# Generated by FakeRAM 2.0
VERSION 5.7 ;
BUSBITCHARS "[]" ;
PROPERTYDEFINITIONS
  MACRO width INTEGER ;
  MACRO depth INTEGER ;
  MACRO banks INTEGER ;
END PROPERTYDEFINITIONS
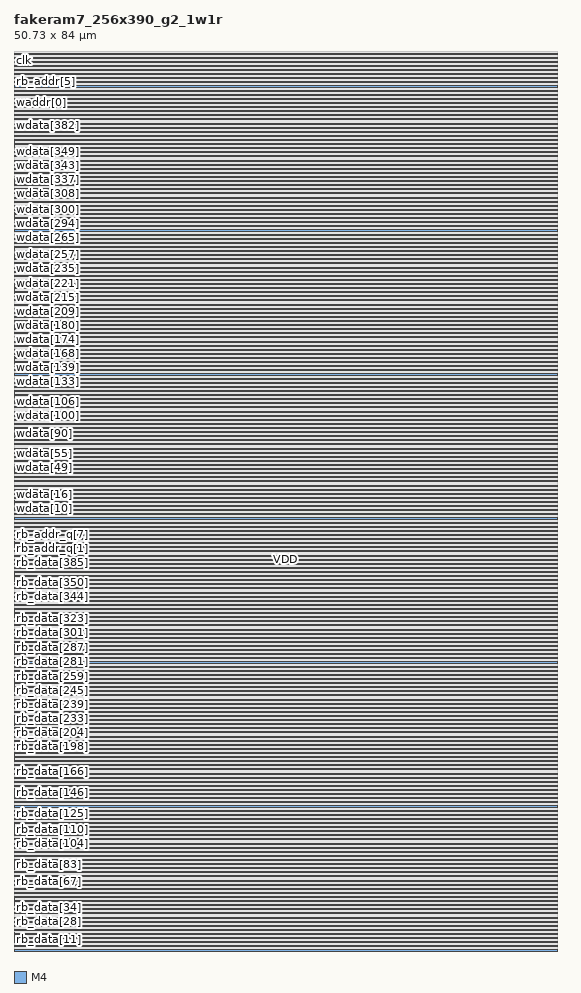
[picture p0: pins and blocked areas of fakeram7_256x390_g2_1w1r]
MACRO fakeram7_256x390_g2_1w1r
  PROPERTY width 390 ;
  PROPERTY depth 256 ;
  PROPERTY banks 1 ;
  FOREIGN fakeram7_256x390_g2_1w1r 0 0 ;
  SYMMETRY X Y R90 ;
  SIZE 50.7300 BY 84.0000 ;
  CLASS BLOCK ;
  PIN wdata[0]
    DIRECTION INPUT ;
    USE SIGNAL ;
    PORT
      LAYER M4 ;
      RECT 0.00000 40.36800 0.02400 40.39200 ;
    END
  END wdata[0]
  PIN wdata[1]
    DIRECTION INPUT ;
    USE SIGNAL ;
    PORT
      LAYER M4 ;
      RECT 0.00000 40.46400 0.02400 40.48800 ;
    END
  END wdata[1]
  PIN wdata[2]
    DIRECTION INPUT ;
    USE SIGNAL ;
    PORT
      LAYER M4 ;
      RECT 0.00000 40.56000 0.02400 40.58400 ;
    END
  END wdata[2]
  PIN wdata[3]
    DIRECTION INPUT ;
    USE SIGNAL ;
    PORT
      LAYER M4 ;
      RECT 0.00000 40.65600 0.02400 40.68000 ;
    END
  END wdata[3]
  PIN wdata[4]
    DIRECTION INPUT ;
    USE SIGNAL ;
    PORT
      LAYER M4 ;
      RECT 0.00000 40.75200 0.02400 40.77600 ;
    END
  END wdata[4]
  PIN wdata[5]
    DIRECTION INPUT ;
    USE SIGNAL ;
    PORT
      LAYER M4 ;
      RECT 0.00000 40.84800 0.02400 40.87200 ;
    END
  END wdata[5]
  PIN wdata[6]
    DIRECTION INPUT ;
    USE SIGNAL ;
    PORT
      LAYER M4 ;
      RECT 0.00000 40.94400 0.02400 40.96800 ;
    END
  END wdata[6]
  PIN wdata[7]
    DIRECTION INPUT ;
    USE SIGNAL ;
    PORT
      LAYER M4 ;
      RECT 0.00000 41.04000 0.02400 41.06400 ;
    END
  END wdata[7]
  PIN wdata[8]
    DIRECTION INPUT ;
    USE SIGNAL ;
    PORT
      LAYER M4 ;
      RECT 0.00000 41.13600 0.02400 41.16000 ;
    END
  END wdata[8]
  PIN wdata[9]
    DIRECTION INPUT ;
    USE SIGNAL ;
    PORT
      LAYER M4 ;
      RECT 0.00000 41.23200 0.02400 41.25600 ;
    END
  END wdata[9]
  PIN wdata[10]
    DIRECTION INPUT ;
    USE SIGNAL ;
    PORT
      LAYER M4 ;
      RECT 0.00000 41.32800 0.02400 41.35200 ;
    END
  END wdata[10]
  PIN wdata[11]
    DIRECTION INPUT ;
    USE SIGNAL ;
    PORT
      LAYER M4 ;
      RECT 0.00000 41.42400 0.02400 41.44800 ;
    END
  END wdata[11]
  PIN wdata[12]
    DIRECTION INPUT ;
    USE SIGNAL ;
    PORT
      LAYER M4 ;
      RECT 0.00000 41.52000 0.02400 41.54400 ;
    END
  END wdata[12]
  PIN wdata[13]
    DIRECTION INPUT ;
    USE SIGNAL ;
    PORT
      LAYER M4 ;
      RECT 0.00000 41.61600 0.02400 41.64000 ;
    END
  END wdata[13]
  PIN wdata[14]
    DIRECTION INPUT ;
    USE SIGNAL ;
    PORT
      LAYER M4 ;
      RECT 0.00000 41.71200 0.02400 41.73600 ;
    END
  END wdata[14]
  PIN wdata[15]
    DIRECTION INPUT ;
    USE SIGNAL ;
    PORT
      LAYER M4 ;
      RECT 0.00000 41.80800 0.02400 41.83200 ;
    END
  END wdata[15]
  PIN wdata[16]
    DIRECTION INPUT ;
    USE SIGNAL ;
    PORT
      LAYER M4 ;
      RECT 0.00000 41.90400 0.02400 41.92800 ;
    END
  END wdata[16]
  PIN wdata[17]
    DIRECTION INPUT ;
    USE SIGNAL ;
    PORT
      LAYER M4 ;
      RECT 0.00000 42.00000 0.02400 42.02400 ;
    END
  END wdata[17]
  PIN wdata[18]
    DIRECTION INPUT ;
    USE SIGNAL ;
    PORT
      LAYER M4 ;
      RECT 0.00000 42.09600 0.02400 42.12000 ;
    END
  END wdata[18]
  PIN wdata[19]
    DIRECTION INPUT ;
    USE SIGNAL ;
    PORT
      LAYER M4 ;
      RECT 0.00000 42.19200 0.02400 42.21600 ;
    END
  END wdata[19]
  PIN wdata[20]
    DIRECTION INPUT ;
    USE SIGNAL ;
    PORT
      LAYER M4 ;
      RECT 0.00000 42.28800 0.02400 42.31200 ;
    END
  END wdata[20]
  PIN wdata[21]
    DIRECTION INPUT ;
    USE SIGNAL ;
    PORT
      LAYER M4 ;
      RECT 0.00000 42.38400 0.02400 42.40800 ;
    END
  END wdata[21]
  PIN wdata[22]
    DIRECTION INPUT ;
    USE SIGNAL ;
    PORT
      LAYER M4 ;
      RECT 0.00000 42.48000 0.02400 42.50400 ;
    END
  END wdata[22]
  PIN wdata[23]
    DIRECTION INPUT ;
    USE SIGNAL ;
    PORT
      LAYER M4 ;
      RECT 0.00000 42.57600 0.02400 42.60000 ;
    END
  END wdata[23]
  PIN wdata[24]
    DIRECTION INPUT ;
    USE SIGNAL ;
    PORT
      LAYER M4 ;
      RECT 0.00000 42.67200 0.02400 42.69600 ;
    END
  END wdata[24]
  PIN wdata[25]
    DIRECTION INPUT ;
    USE SIGNAL ;
    PORT
      LAYER M4 ;
      RECT 0.00000 42.76800 0.02400 42.79200 ;
    END
  END wdata[25]
  PIN wdata[26]
    DIRECTION INPUT ;
    USE SIGNAL ;
    PORT
      LAYER M4 ;
      RECT 0.00000 42.86400 0.02400 42.88800 ;
    END
  END wdata[26]
  PIN wdata[27]
    DIRECTION INPUT ;
    USE SIGNAL ;
    PORT
      LAYER M4 ;
      RECT 0.00000 42.96000 0.02400 42.98400 ;
    END
  END wdata[27]
  PIN wdata[28]
    DIRECTION INPUT ;
    USE SIGNAL ;
    PORT
      LAYER M4 ;
      RECT 0.00000 43.05600 0.02400 43.08000 ;
    END
  END wdata[28]
  PIN wdata[29]
    DIRECTION INPUT ;
    USE SIGNAL ;
    PORT
      LAYER M4 ;
      RECT 0.00000 43.15200 0.02400 43.17600 ;
    END
  END wdata[29]
  PIN wdata[30]
    DIRECTION INPUT ;
    USE SIGNAL ;
    PORT
      LAYER M4 ;
      RECT 0.00000 43.24800 0.02400 43.27200 ;
    END
  END wdata[30]
  PIN wdata[31]
    DIRECTION INPUT ;
    USE SIGNAL ;
    PORT
      LAYER M4 ;
      RECT 0.00000 43.34400 0.02400 43.36800 ;
    END
  END wdata[31]
  PIN wdata[32]
    DIRECTION INPUT ;
    USE SIGNAL ;
    PORT
      LAYER M4 ;
      RECT 0.00000 43.44000 0.02400 43.46400 ;
    END
  END wdata[32]
  PIN wdata[33]
    DIRECTION INPUT ;
    USE SIGNAL ;
    PORT
      LAYER M4 ;
      RECT 0.00000 43.53600 0.02400 43.56000 ;
    END
  END wdata[33]
  PIN wdata[34]
    DIRECTION INPUT ;
    USE SIGNAL ;
    PORT
      LAYER M4 ;
      RECT 0.00000 43.63200 0.02400 43.65600 ;
    END
  END wdata[34]
  PIN wdata[35]
    DIRECTION INPUT ;
    USE SIGNAL ;
    PORT
      LAYER M4 ;
      RECT 0.00000 43.72800 0.02400 43.75200 ;
    END
  END wdata[35]
  PIN wdata[36]
    DIRECTION INPUT ;
    USE SIGNAL ;
    PORT
      LAYER M4 ;
      RECT 0.00000 43.82400 0.02400 43.84800 ;
    END
  END wdata[36]
  PIN wdata[37]
    DIRECTION INPUT ;
    USE SIGNAL ;
    PORT
      LAYER M4 ;
      RECT 0.00000 43.92000 0.02400 43.94400 ;
    END
  END wdata[37]
  PIN wdata[38]
    DIRECTION INPUT ;
    USE SIGNAL ;
    PORT
      LAYER M4 ;
      RECT 0.00000 44.01600 0.02400 44.04000 ;
    END
  END wdata[38]
  PIN wdata[39]
    DIRECTION INPUT ;
    USE SIGNAL ;
    PORT
      LAYER M4 ;
      RECT 0.00000 44.11200 0.02400 44.13600 ;
    END
  END wdata[39]
  PIN wdata[40]
    DIRECTION INPUT ;
    USE SIGNAL ;
    PORT
      LAYER M4 ;
      RECT 0.00000 44.20800 0.02400 44.23200 ;
    END
  END wdata[40]
  PIN wdata[41]
    DIRECTION INPUT ;
    USE SIGNAL ;
    PORT
      LAYER M4 ;
      RECT 0.00000 44.30400 0.02400 44.32800 ;
    END
  END wdata[41]
  PIN wdata[42]
    DIRECTION INPUT ;
    USE SIGNAL ;
    PORT
      LAYER M4 ;
      RECT 0.00000 44.40000 0.02400 44.42400 ;
    END
  END wdata[42]
  PIN wdata[43]
    DIRECTION INPUT ;
    USE SIGNAL ;
    PORT
      LAYER M4 ;
      RECT 0.00000 44.49600 0.02400 44.52000 ;
    END
  END wdata[43]
  PIN wdata[44]
    DIRECTION INPUT ;
    USE SIGNAL ;
    PORT
      LAYER M4 ;
      RECT 0.00000 44.59200 0.02400 44.61600 ;
    END
  END wdata[44]
  PIN wdata[45]
    DIRECTION INPUT ;
    USE SIGNAL ;
    PORT
      LAYER M4 ;
      RECT 0.00000 44.68800 0.02400 44.71200 ;
    END
  END wdata[45]
  PIN wdata[46]
    DIRECTION INPUT ;
    USE SIGNAL ;
    PORT
      LAYER M4 ;
      RECT 0.00000 44.78400 0.02400 44.80800 ;
    END
  END wdata[46]
  PIN wdata[47]
    DIRECTION INPUT ;
    USE SIGNAL ;
    PORT
      LAYER M4 ;
      RECT 0.00000 44.88000 0.02400 44.90400 ;
    END
  END wdata[47]
  PIN wdata[48]
    DIRECTION INPUT ;
    USE SIGNAL ;
    PORT
      LAYER M4 ;
      RECT 0.00000 44.97600 0.02400 45.00000 ;
    END
  END wdata[48]
  PIN wdata[49]
    DIRECTION INPUT ;
    USE SIGNAL ;
    PORT
      LAYER M4 ;
      RECT 0.00000 45.07200 0.02400 45.09600 ;
    END
  END wdata[49]
  PIN wdata[50]
    DIRECTION INPUT ;
    USE SIGNAL ;
    PORT
      LAYER M4 ;
      RECT 0.00000 45.16800 0.02400 45.19200 ;
    END
  END wdata[50]
  PIN wdata[51]
    DIRECTION INPUT ;
    USE SIGNAL ;
    PORT
      LAYER M4 ;
      RECT 0.00000 45.26400 0.02400 45.28800 ;
    END
  END wdata[51]
  PIN wdata[52]
    DIRECTION INPUT ;
    USE SIGNAL ;
    PORT
      LAYER M4 ;
      RECT 0.00000 45.36000 0.02400 45.38400 ;
    END
  END wdata[52]
  PIN wdata[53]
    DIRECTION INPUT ;
    USE SIGNAL ;
    PORT
      LAYER M4 ;
      RECT 0.00000 45.45600 0.02400 45.48000 ;
    END
  END wdata[53]
  PIN wdata[54]
    DIRECTION INPUT ;
    USE SIGNAL ;
    PORT
      LAYER M4 ;
      RECT 0.00000 45.55200 0.02400 45.57600 ;
    END
  END wdata[54]
  PIN wdata[55]
    DIRECTION INPUT ;
    USE SIGNAL ;
    PORT
      LAYER M4 ;
      RECT 0.00000 45.64800 0.02400 45.67200 ;
    END
  END wdata[55]
  PIN wdata[56]
    DIRECTION INPUT ;
    USE SIGNAL ;
    PORT
      LAYER M4 ;
      RECT 0.00000 45.74400 0.02400 45.76800 ;
    END
  END wdata[56]
  PIN wdata[57]
    DIRECTION INPUT ;
    USE SIGNAL ;
    PORT
      LAYER M4 ;
      RECT 0.00000 45.84000 0.02400 45.86400 ;
    END
  END wdata[57]
  PIN wdata[58]
    DIRECTION INPUT ;
    USE SIGNAL ;
    PORT
      LAYER M4 ;
      RECT 0.00000 45.93600 0.02400 45.96000 ;
    END
  END wdata[58]
  PIN wdata[59]
    DIRECTION INPUT ;
    USE SIGNAL ;
    PORT
      LAYER M4 ;
      RECT 0.00000 46.03200 0.02400 46.05600 ;
    END
  END wdata[59]
  PIN wdata[60]
    DIRECTION INPUT ;
    USE SIGNAL ;
    PORT
      LAYER M4 ;
      RECT 0.00000 46.12800 0.02400 46.15200 ;
    END
  END wdata[60]
  PIN wdata[61]
    DIRECTION INPUT ;
    USE SIGNAL ;
    PORT
      LAYER M4 ;
      RECT 0.00000 46.22400 0.02400 46.24800 ;
    END
  END wdata[61]
  PIN wdata[62]
    DIRECTION INPUT ;
    USE SIGNAL ;
    PORT
      LAYER M4 ;
      RECT 0.00000 46.32000 0.02400 46.34400 ;
    END
  END wdata[62]
  PIN wdata[63]
    DIRECTION INPUT ;
    USE SIGNAL ;
    PORT
      LAYER M4 ;
      RECT 0.00000 46.41600 0.02400 46.44000 ;
    END
  END wdata[63]
  PIN wdata[64]
    DIRECTION INPUT ;
    USE SIGNAL ;
    PORT
      LAYER M4 ;
      RECT 0.00000 46.51200 0.02400 46.53600 ;
    END
  END wdata[64]
  PIN wdata[65]
    DIRECTION INPUT ;
    USE SIGNAL ;
    PORT
      LAYER M4 ;
      RECT 0.00000 46.60800 0.02400 46.63200 ;
    END
  END wdata[65]
  PIN wdata[66]
    DIRECTION INPUT ;
    USE SIGNAL ;
    PORT
      LAYER M4 ;
      RECT 0.00000 46.70400 0.02400 46.72800 ;
    END
  END wdata[66]
  PIN wdata[67]
    DIRECTION INPUT ;
    USE SIGNAL ;
    PORT
      LAYER M4 ;
      RECT 0.00000 46.80000 0.02400 46.82400 ;
    END
  END wdata[67]
  PIN wdata[68]
    DIRECTION INPUT ;
    USE SIGNAL ;
    PORT
      LAYER M4 ;
      RECT 0.00000 46.89600 0.02400 46.92000 ;
    END
  END wdata[68]
  PIN wdata[69]
    DIRECTION INPUT ;
    USE SIGNAL ;
    PORT
      LAYER M4 ;
      RECT 0.00000 46.99200 0.02400 47.01600 ;
    END
  END wdata[69]
  PIN wdata[70]
    DIRECTION INPUT ;
    USE SIGNAL ;
    PORT
      LAYER M4 ;
      RECT 0.00000 47.08800 0.02400 47.11200 ;
    END
  END wdata[70]
  PIN wdata[71]
    DIRECTION INPUT ;
    USE SIGNAL ;
    PORT
      LAYER M4 ;
      RECT 0.00000 47.18400 0.02400 47.20800 ;
    END
  END wdata[71]
  PIN wdata[72]
    DIRECTION INPUT ;
    USE SIGNAL ;
    PORT
      LAYER M4 ;
      RECT 0.00000 47.28000 0.02400 47.30400 ;
    END
  END wdata[72]
  PIN wdata[73]
    DIRECTION INPUT ;
    USE SIGNAL ;
    PORT
      LAYER M4 ;
      RECT 0.00000 47.37600 0.02400 47.40000 ;
    END
  END wdata[73]
  PIN wdata[74]
    DIRECTION INPUT ;
    USE SIGNAL ;
    PORT
      LAYER M4 ;
      RECT 0.00000 47.47200 0.02400 47.49600 ;
    END
  END wdata[74]
  PIN wdata[75]
    DIRECTION INPUT ;
    USE SIGNAL ;
    PORT
      LAYER M4 ;
      RECT 0.00000 47.56800 0.02400 47.59200 ;
    END
  END wdata[75]
  PIN wdata[76]
    DIRECTION INPUT ;
    USE SIGNAL ;
    PORT
      LAYER M4 ;
      RECT 0.00000 47.66400 0.02400 47.68800 ;
    END
  END wdata[76]
  PIN wdata[77]
    DIRECTION INPUT ;
    USE SIGNAL ;
    PORT
      LAYER M4 ;
      RECT 0.00000 47.76000 0.02400 47.78400 ;
    END
  END wdata[77]
  PIN wdata[78]
    DIRECTION INPUT ;
    USE SIGNAL ;
    PORT
      LAYER M4 ;
      RECT 0.00000 47.85600 0.02400 47.88000 ;
    END
  END wdata[78]
  PIN wdata[79]
    DIRECTION INPUT ;
    USE SIGNAL ;
    PORT
      LAYER M4 ;
      RECT 0.00000 47.95200 0.02400 47.97600 ;
    END
  END wdata[79]
  PIN wdata[80]
    DIRECTION INPUT ;
    USE SIGNAL ;
    PORT
      LAYER M4 ;
      RECT 0.00000 48.04800 0.02400 48.07200 ;
    END
  END wdata[80]
  PIN wdata[81]
    DIRECTION INPUT ;
    USE SIGNAL ;
    PORT
      LAYER M4 ;
      RECT 0.00000 48.14400 0.02400 48.16800 ;
    END
  END wdata[81]
  PIN wdata[82]
    DIRECTION INPUT ;
    USE SIGNAL ;
    PORT
      LAYER M4 ;
      RECT 0.00000 48.24000 0.02400 48.26400 ;
    END
  END wdata[82]
  PIN wdata[83]
    DIRECTION INPUT ;
    USE SIGNAL ;
    PORT
      LAYER M4 ;
      RECT 0.00000 48.33600 0.02400 48.36000 ;
    END
  END wdata[83]
  PIN wdata[84]
    DIRECTION INPUT ;
    USE SIGNAL ;
    PORT
      LAYER M4 ;
      RECT 0.00000 48.43200 0.02400 48.45600 ;
    END
  END wdata[84]
  PIN wdata[85]
    DIRECTION INPUT ;
    USE SIGNAL ;
    PORT
      LAYER M4 ;
      RECT 0.00000 48.52800 0.02400 48.55200 ;
    END
  END wdata[85]
  PIN wdata[86]
    DIRECTION INPUT ;
    USE SIGNAL ;
    PORT
      LAYER M4 ;
      RECT 0.00000 48.62400 0.02400 48.64800 ;
    END
  END wdata[86]
  PIN wdata[87]
    DIRECTION INPUT ;
    USE SIGNAL ;
    PORT
      LAYER M4 ;
      RECT 0.00000 48.72000 0.02400 48.74400 ;
    END
  END wdata[87]
  PIN wdata[88]
    DIRECTION INPUT ;
    USE SIGNAL ;
    PORT
      LAYER M4 ;
      RECT 0.00000 48.81600 0.02400 48.84000 ;
    END
  END wdata[88]
  PIN wdata[89]
    DIRECTION INPUT ;
    USE SIGNAL ;
    PORT
      LAYER M4 ;
      RECT 0.00000 48.91200 0.02400 48.93600 ;
    END
  END wdata[89]
  PIN wdata[90]
    DIRECTION INPUT ;
    USE SIGNAL ;
    PORT
      LAYER M4 ;
      RECT 0.00000 49.00800 0.02400 49.03200 ;
    END
  END wdata[90]
  PIN wdata[91]
    DIRECTION INPUT ;
    USE SIGNAL ;
    PORT
      LAYER M4 ;
      RECT 0.00000 49.10400 0.02400 49.12800 ;
    END
  END wdata[91]
  PIN wdata[92]
    DIRECTION INPUT ;
    USE SIGNAL ;
    PORT
      LAYER M4 ;
      RECT 0.00000 49.20000 0.02400 49.22400 ;
    END
  END wdata[92]
  PIN wdata[93]
    DIRECTION INPUT ;
    USE SIGNAL ;
    PORT
      LAYER M4 ;
      RECT 0.00000 49.29600 0.02400 49.32000 ;
    END
  END wdata[93]
  PIN wdata[94]
    DIRECTION INPUT ;
    USE SIGNAL ;
    PORT
      LAYER M4 ;
      RECT 0.00000 49.39200 0.02400 49.41600 ;
    END
  END wdata[94]
  PIN wdata[95]
    DIRECTION INPUT ;
    USE SIGNAL ;
    PORT
      LAYER M4 ;
      RECT 0.00000 49.48800 0.02400 49.51200 ;
    END
  END wdata[95]
  PIN wdata[96]
    DIRECTION INPUT ;
    USE SIGNAL ;
    PORT
      LAYER M4 ;
      RECT 0.00000 49.58400 0.02400 49.60800 ;
    END
  END wdata[96]
  PIN wdata[97]
    DIRECTION INPUT ;
    USE SIGNAL ;
    PORT
      LAYER M4 ;
      RECT 0.00000 49.68000 0.02400 49.70400 ;
    END
  END wdata[97]
  PIN wdata[98]
    DIRECTION INPUT ;
    USE SIGNAL ;
    PORT
      LAYER M4 ;
      RECT 0.00000 49.77600 0.02400 49.80000 ;
    END
  END wdata[98]
  PIN wdata[99]
    DIRECTION INPUT ;
    USE SIGNAL ;
    PORT
      LAYER M4 ;
      RECT 0.00000 49.87200 0.02400 49.89600 ;
    END
  END wdata[99]
  PIN wdata[100]
    DIRECTION INPUT ;
    USE SIGNAL ;
    PORT
      LAYER M4 ;
      RECT 0.00000 49.96800 0.02400 49.99200 ;
    END
  END wdata[100]
  PIN wdata[101]
    DIRECTION INPUT ;
    USE SIGNAL ;
    PORT
      LAYER M4 ;
      RECT 0.00000 50.06400 0.02400 50.08800 ;
    END
  END wdata[101]
  PIN wdata[102]
    DIRECTION INPUT ;
    USE SIGNAL ;
    PORT
      LAYER M4 ;
      RECT 0.00000 50.16000 0.02400 50.18400 ;
    END
  END wdata[102]
  PIN wdata[103]
    DIRECTION INPUT ;
    USE SIGNAL ;
    PORT
      LAYER M4 ;
      RECT 0.00000 50.25600 0.02400 50.28000 ;
    END
  END wdata[103]
  PIN wdata[104]
    DIRECTION INPUT ;
    USE SIGNAL ;
    PORT
      LAYER M4 ;
      RECT 0.00000 50.35200 0.02400 50.37600 ;
    END
  END wdata[104]
  PIN wdata[105]
    DIRECTION INPUT ;
    USE SIGNAL ;
    PORT
      LAYER M4 ;
      RECT 0.00000 50.44800 0.02400 50.47200 ;
    END
  END wdata[105]
  PIN wdata[106]
    DIRECTION INPUT ;
    USE SIGNAL ;
    PORT
      LAYER M4 ;
      RECT 0.00000 50.54400 0.02400 50.56800 ;
    END
  END wdata[106]
  PIN wdata[107]
    DIRECTION INPUT ;
    USE SIGNAL ;
    PORT
      LAYER M4 ;
      RECT 0.00000 50.64000 0.02400 50.66400 ;
    END
  END wdata[107]
  PIN wdata[108]
    DIRECTION INPUT ;
    USE SIGNAL ;
    PORT
      LAYER M4 ;
      RECT 0.00000 50.73600 0.02400 50.76000 ;
    END
  END wdata[108]
  PIN wdata[109]
    DIRECTION INPUT ;
    USE SIGNAL ;
    PORT
      LAYER M4 ;
      RECT 0.00000 50.83200 0.02400 50.85600 ;
    END
  END wdata[109]
  PIN wdata[110]
    DIRECTION INPUT ;
    USE SIGNAL ;
    PORT
      LAYER M4 ;
      RECT 0.00000 50.92800 0.02400 50.95200 ;
    END
  END wdata[110]
  PIN wdata[111]
    DIRECTION INPUT ;
    USE SIGNAL ;
    PORT
      LAYER M4 ;
      RECT 0.00000 51.02400 0.02400 51.04800 ;
    END
  END wdata[111]
  PIN wdata[112]
    DIRECTION INPUT ;
    USE SIGNAL ;
    PORT
      LAYER M4 ;
      RECT 0.00000 51.12000 0.02400 51.14400 ;
    END
  END wdata[112]
  PIN wdata[113]
    DIRECTION INPUT ;
    USE SIGNAL ;
    PORT
      LAYER M4 ;
      RECT 0.00000 51.21600 0.02400 51.24000 ;
    END
  END wdata[113]
  PIN wdata[114]
    DIRECTION INPUT ;
    USE SIGNAL ;
    PORT
      LAYER M4 ;
      RECT 0.00000 51.31200 0.02400 51.33600 ;
    END
  END wdata[114]
  PIN wdata[115]
    DIRECTION INPUT ;
    USE SIGNAL ;
    PORT
      LAYER M4 ;
      RECT 0.00000 51.40800 0.02400 51.43200 ;
    END
  END wdata[115]
  PIN wdata[116]
    DIRECTION INPUT ;
    USE SIGNAL ;
    PORT
      LAYER M4 ;
      RECT 0.00000 51.50400 0.02400 51.52800 ;
    END
  END wdata[116]
  PIN wdata[117]
    DIRECTION INPUT ;
    USE SIGNAL ;
    PORT
      LAYER M4 ;
      RECT 0.00000 51.60000 0.02400 51.62400 ;
    END
  END wdata[117]
  PIN wdata[118]
    DIRECTION INPUT ;
    USE SIGNAL ;
    PORT
      LAYER M4 ;
      RECT 0.00000 51.69600 0.02400 51.72000 ;
    END
  END wdata[118]
  PIN wdata[119]
    DIRECTION INPUT ;
    USE SIGNAL ;
    PORT
      LAYER M4 ;
      RECT 0.00000 51.79200 0.02400 51.81600 ;
    END
  END wdata[119]
  PIN wdata[120]
    DIRECTION INPUT ;
    USE SIGNAL ;
    PORT
      LAYER M4 ;
      RECT 0.00000 51.88800 0.02400 51.91200 ;
    END
  END wdata[120]
  PIN wdata[121]
    DIRECTION INPUT ;
    USE SIGNAL ;
    PORT
      LAYER M4 ;
      RECT 0.00000 51.98400 0.02400 52.00800 ;
    END
  END wdata[121]
  PIN wdata[122]
    DIRECTION INPUT ;
    USE SIGNAL ;
    PORT
      LAYER M4 ;
      RECT 0.00000 52.08000 0.02400 52.10400 ;
    END
  END wdata[122]
  PIN wdata[123]
    DIRECTION INPUT ;
    USE SIGNAL ;
    PORT
      LAYER M4 ;
      RECT 0.00000 52.17600 0.02400 52.20000 ;
    END
  END wdata[123]
  PIN wdata[124]
    DIRECTION INPUT ;
    USE SIGNAL ;
    PORT
      LAYER M4 ;
      RECT 0.00000 52.27200 0.02400 52.29600 ;
    END
  END wdata[124]
  PIN wdata[125]
    DIRECTION INPUT ;
    USE SIGNAL ;
    PORT
      LAYER M4 ;
      RECT 0.00000 52.36800 0.02400 52.39200 ;
    END
  END wdata[125]
  PIN wdata[126]
    DIRECTION INPUT ;
    USE SIGNAL ;
    PORT
      LAYER M4 ;
      RECT 0.00000 52.46400 0.02400 52.48800 ;
    END
  END wdata[126]
  PIN wdata[127]
    DIRECTION INPUT ;
    USE SIGNAL ;
    PORT
      LAYER M4 ;
      RECT 0.00000 52.56000 0.02400 52.58400 ;
    END
  END wdata[127]
  PIN wdata[128]
    DIRECTION INPUT ;
    USE SIGNAL ;
    PORT
      LAYER M4 ;
      RECT 0.00000 52.65600 0.02400 52.68000 ;
    END
  END wdata[128]
  PIN wdata[129]
    DIRECTION INPUT ;
    USE SIGNAL ;
    PORT
      LAYER M4 ;
      RECT 0.00000 52.75200 0.02400 52.77600 ;
    END
  END wdata[129]
  PIN wdata[130]
    DIRECTION INPUT ;
    USE SIGNAL ;
    PORT
      LAYER M4 ;
      RECT 0.00000 52.84800 0.02400 52.87200 ;
    END
  END wdata[130]
  PIN wdata[131]
    DIRECTION INPUT ;
    USE SIGNAL ;
    PORT
      LAYER M4 ;
      RECT 0.00000 52.94400 0.02400 52.96800 ;
    END
  END wdata[131]
  PIN wdata[132]
    DIRECTION INPUT ;
    USE SIGNAL ;
    PORT
      LAYER M4 ;
      RECT 0.00000 53.04000 0.02400 53.06400 ;
    END
  END wdata[132]
  PIN wdata[133]
    DIRECTION INPUT ;
    USE SIGNAL ;
    PORT
      LAYER M4 ;
      RECT 0.00000 53.13600 0.02400 53.16000 ;
    END
  END wdata[133]
  PIN wdata[134]
    DIRECTION INPUT ;
    USE SIGNAL ;
    PORT
      LAYER M4 ;
      RECT 0.00000 53.23200 0.02400 53.25600 ;
    END
  END wdata[134]
  PIN wdata[135]
    DIRECTION INPUT ;
    USE SIGNAL ;
    PORT
      LAYER M4 ;
      RECT 0.00000 53.32800 0.02400 53.35200 ;
    END
  END wdata[135]
  PIN wdata[136]
    DIRECTION INPUT ;
    USE SIGNAL ;
    PORT
      LAYER M4 ;
      RECT 0.00000 53.42400 0.02400 53.44800 ;
    END
  END wdata[136]
  PIN wdata[137]
    DIRECTION INPUT ;
    USE SIGNAL ;
    PORT
      LAYER M4 ;
      RECT 0.00000 53.52000 0.02400 53.54400 ;
    END
  END wdata[137]
  PIN wdata[138]
    DIRECTION INPUT ;
    USE SIGNAL ;
    PORT
      LAYER M4 ;
      RECT 0.00000 53.61600 0.02400 53.64000 ;
    END
  END wdata[138]
  PIN wdata[139]
    DIRECTION INPUT ;
    USE SIGNAL ;
    PORT
      LAYER M4 ;
      RECT 0.00000 53.71200 0.02400 53.73600 ;
    END
  END wdata[139]
  PIN wdata[140]
    DIRECTION INPUT ;
    USE SIGNAL ;
    PORT
      LAYER M4 ;
      RECT 0.00000 53.80800 0.02400 53.83200 ;
    END
  END wdata[140]
  PIN wdata[141]
    DIRECTION INPUT ;
    USE SIGNAL ;
    PORT
      LAYER M4 ;
      RECT 0.00000 53.90400 0.02400 53.92800 ;
    END
  END wdata[141]
  PIN wdata[142]
    DIRECTION INPUT ;
    USE SIGNAL ;
    PORT
      LAYER M4 ;
      RECT 0.00000 54.00000 0.02400 54.02400 ;
    END
  END wdata[142]
  PIN wdata[143]
    DIRECTION INPUT ;
    USE SIGNAL ;
    PORT
      LAYER M4 ;
      RECT 0.00000 54.09600 0.02400 54.12000 ;
    END
  END wdata[143]
  PIN wdata[144]
    DIRECTION INPUT ;
    USE SIGNAL ;
    PORT
      LAYER M4 ;
      RECT 0.00000 54.19200 0.02400 54.21600 ;
    END
  END wdata[144]
  PIN wdata[145]
    DIRECTION INPUT ;
    USE SIGNAL ;
    PORT
      LAYER M4 ;
      RECT 0.00000 54.28800 0.02400 54.31200 ;
    END
  END wdata[145]
  PIN wdata[146]
    DIRECTION INPUT ;
    USE SIGNAL ;
    PORT
      LAYER M4 ;
      RECT 0.00000 54.38400 0.02400 54.40800 ;
    END
  END wdata[146]
  PIN wdata[147]
    DIRECTION INPUT ;
    USE SIGNAL ;
    PORT
      LAYER M4 ;
      RECT 0.00000 54.48000 0.02400 54.50400 ;
    END
  END wdata[147]
  PIN wdata[148]
    DIRECTION INPUT ;
    USE SIGNAL ;
    PORT
      LAYER M4 ;
      RECT 0.00000 54.57600 0.02400 54.60000 ;
    END
  END wdata[148]
  PIN wdata[149]
    DIRECTION INPUT ;
    USE SIGNAL ;
    PORT
      LAYER M4 ;
      RECT 0.00000 54.67200 0.02400 54.69600 ;
    END
  END wdata[149]
  PIN wdata[150]
    DIRECTION INPUT ;
    USE SIGNAL ;
    PORT
      LAYER M4 ;
      RECT 0.00000 54.76800 0.02400 54.79200 ;
    END
  END wdata[150]
  PIN wdata[151]
    DIRECTION INPUT ;
    USE SIGNAL ;
    PORT
      LAYER M4 ;
      RECT 0.00000 54.86400 0.02400 54.88800 ;
    END
  END wdata[151]
  PIN wdata[152]
    DIRECTION INPUT ;
    USE SIGNAL ;
    PORT
      LAYER M4 ;
      RECT 0.00000 54.96000 0.02400 54.98400 ;
    END
  END wdata[152]
  PIN wdata[153]
    DIRECTION INPUT ;
    USE SIGNAL ;
    PORT
      LAYER M4 ;
      RECT 0.00000 55.05600 0.02400 55.08000 ;
    END
  END wdata[153]
  PIN wdata[154]
    DIRECTION INPUT ;
    USE SIGNAL ;
    PORT
      LAYER M4 ;
      RECT 0.00000 55.15200 0.02400 55.17600 ;
    END
  END wdata[154]
  PIN wdata[155]
    DIRECTION INPUT ;
    USE SIGNAL ;
    PORT
      LAYER M4 ;
      RECT 0.00000 55.24800 0.02400 55.27200 ;
    END
  END wdata[155]
  PIN wdata[156]
    DIRECTION INPUT ;
    USE SIGNAL ;
    PORT
      LAYER M4 ;
      RECT 0.00000 55.34400 0.02400 55.36800 ;
    END
  END wdata[156]
  PIN wdata[157]
    DIRECTION INPUT ;
    USE SIGNAL ;
    PORT
      LAYER M4 ;
      RECT 0.00000 55.44000 0.02400 55.46400 ;
    END
  END wdata[157]
  PIN wdata[158]
    DIRECTION INPUT ;
    USE SIGNAL ;
    PORT
      LAYER M4 ;
      RECT 0.00000 55.53600 0.02400 55.56000 ;
    END
  END wdata[158]
  PIN wdata[159]
    DIRECTION INPUT ;
    USE SIGNAL ;
    PORT
      LAYER M4 ;
      RECT 0.00000 55.63200 0.02400 55.65600 ;
    END
  END wdata[159]
  PIN wdata[160]
    DIRECTION INPUT ;
    USE SIGNAL ;
    PORT
      LAYER M4 ;
      RECT 0.00000 55.72800 0.02400 55.75200 ;
    END
  END wdata[160]
  PIN wdata[161]
    DIRECTION INPUT ;
    USE SIGNAL ;
    PORT
      LAYER M4 ;
      RECT 0.00000 55.82400 0.02400 55.84800 ;
    END
  END wdata[161]
  PIN wdata[162]
    DIRECTION INPUT ;
    USE SIGNAL ;
    PORT
      LAYER M4 ;
      RECT 0.00000 55.92000 0.02400 55.94400 ;
    END
  END wdata[162]
  PIN wdata[163]
    DIRECTION INPUT ;
    USE SIGNAL ;
    PORT
      LAYER M4 ;
      RECT 0.00000 56.01600 0.02400 56.04000 ;
    END
  END wdata[163]
  PIN wdata[164]
    DIRECTION INPUT ;
    USE SIGNAL ;
    PORT
      LAYER M4 ;
      RECT 0.00000 56.11200 0.02400 56.13600 ;
    END
  END wdata[164]
  PIN wdata[165]
    DIRECTION INPUT ;
    USE SIGNAL ;
    PORT
      LAYER M4 ;
      RECT 0.00000 56.20800 0.02400 56.23200 ;
    END
  END wdata[165]
  PIN wdata[166]
    DIRECTION INPUT ;
    USE SIGNAL ;
    PORT
      LAYER M4 ;
      RECT 0.00000 56.30400 0.02400 56.32800 ;
    END
  END wdata[166]
  PIN wdata[167]
    DIRECTION INPUT ;
    USE SIGNAL ;
    PORT
      LAYER M4 ;
      RECT 0.00000 56.40000 0.02400 56.42400 ;
    END
  END wdata[167]
  PIN wdata[168]
    DIRECTION INPUT ;
    USE SIGNAL ;
    PORT
      LAYER M4 ;
      RECT 0.00000 56.49600 0.02400 56.52000 ;
    END
  END wdata[168]
  PIN wdata[169]
    DIRECTION INPUT ;
    USE SIGNAL ;
    PORT
      LAYER M4 ;
      RECT 0.00000 56.59200 0.02400 56.61600 ;
    END
  END wdata[169]
  PIN wdata[170]
    DIRECTION INPUT ;
    USE SIGNAL ;
    PORT
      LAYER M4 ;
      RECT 0.00000 56.68800 0.02400 56.71200 ;
    END
  END wdata[170]
  PIN wdata[171]
    DIRECTION INPUT ;
    USE SIGNAL ;
    PORT
      LAYER M4 ;
      RECT 0.00000 56.78400 0.02400 56.80800 ;
    END
  END wdata[171]
  PIN wdata[172]
    DIRECTION INPUT ;
    USE SIGNAL ;
    PORT
      LAYER M4 ;
      RECT 0.00000 56.88000 0.02400 56.90400 ;
    END
  END wdata[172]
  PIN wdata[173]
    DIRECTION INPUT ;
    USE SIGNAL ;
    PORT
      LAYER M4 ;
      RECT 0.00000 56.97600 0.02400 57.00000 ;
    END
  END wdata[173]
  PIN wdata[174]
    DIRECTION INPUT ;
    USE SIGNAL ;
    PORT
      LAYER M4 ;
      RECT 0.00000 57.07200 0.02400 57.09600 ;
    END
  END wdata[174]
  PIN wdata[175]
    DIRECTION INPUT ;
    USE SIGNAL ;
    PORT
      LAYER M4 ;
      RECT 0.00000 57.16800 0.02400 57.19200 ;
    END
  END wdata[175]
  PIN wdata[176]
    DIRECTION INPUT ;
    USE SIGNAL ;
    PORT
      LAYER M4 ;
      RECT 0.00000 57.26400 0.02400 57.28800 ;
    END
  END wdata[176]
  PIN wdata[177]
    DIRECTION INPUT ;
    USE SIGNAL ;
    PORT
      LAYER M4 ;
      RECT 0.00000 57.36000 0.02400 57.38400 ;
    END
  END wdata[177]
  PIN wdata[178]
    DIRECTION INPUT ;
    USE SIGNAL ;
    PORT
      LAYER M4 ;
      RECT 0.00000 57.45600 0.02400 57.48000 ;
    END
  END wdata[178]
  PIN wdata[179]
    DIRECTION INPUT ;
    USE SIGNAL ;
    PORT
      LAYER M4 ;
      RECT 0.00000 57.55200 0.02400 57.57600 ;
    END
  END wdata[179]
  PIN wdata[180]
    DIRECTION INPUT ;
    USE SIGNAL ;
    PORT
      LAYER M4 ;
      RECT 0.00000 57.64800 0.02400 57.67200 ;
    END
  END wdata[180]
  PIN wdata[181]
    DIRECTION INPUT ;
    USE SIGNAL ;
    PORT
      LAYER M4 ;
      RECT 0.00000 57.74400 0.02400 57.76800 ;
    END
  END wdata[181]
  PIN wdata[182]
    DIRECTION INPUT ;
    USE SIGNAL ;
    PORT
      LAYER M4 ;
      RECT 0.00000 57.84000 0.02400 57.86400 ;
    END
  END wdata[182]
  PIN wdata[183]
    DIRECTION INPUT ;
    USE SIGNAL ;
    PORT
      LAYER M4 ;
      RECT 0.00000 57.93600 0.02400 57.96000 ;
    END
  END wdata[183]
  PIN wdata[184]
    DIRECTION INPUT ;
    USE SIGNAL ;
    PORT
      LAYER M4 ;
      RECT 0.00000 58.03200 0.02400 58.05600 ;
    END
  END wdata[184]
  PIN wdata[185]
    DIRECTION INPUT ;
    USE SIGNAL ;
    PORT
      LAYER M4 ;
      RECT 0.00000 58.12800 0.02400 58.15200 ;
    END
  END wdata[185]
  PIN wdata[186]
    DIRECTION INPUT ;
    USE SIGNAL ;
    PORT
      LAYER M4 ;
      RECT 0.00000 58.22400 0.02400 58.24800 ;
    END
  END wdata[186]
  PIN wdata[187]
    DIRECTION INPUT ;
    USE SIGNAL ;
    PORT
      LAYER M4 ;
      RECT 0.00000 58.32000 0.02400 58.34400 ;
    END
  END wdata[187]
  PIN wdata[188]
    DIRECTION INPUT ;
    USE SIGNAL ;
    PORT
      LAYER M4 ;
      RECT 0.00000 58.41600 0.02400 58.44000 ;
    END
  END wdata[188]
  PIN wdata[189]
    DIRECTION INPUT ;
    USE SIGNAL ;
    PORT
      LAYER M4 ;
      RECT 0.00000 58.51200 0.02400 58.53600 ;
    END
  END wdata[189]
  PIN wdata[190]
    DIRECTION INPUT ;
    USE SIGNAL ;
    PORT
      LAYER M4 ;
      RECT 0.00000 58.60800 0.02400 58.63200 ;
    END
  END wdata[190]
  PIN wdata[191]
    DIRECTION INPUT ;
    USE SIGNAL ;
    PORT
      LAYER M4 ;
      RECT 0.00000 58.70400 0.02400 58.72800 ;
    END
  END wdata[191]
  PIN wdata[192]
    DIRECTION INPUT ;
    USE SIGNAL ;
    PORT
      LAYER M4 ;
      RECT 0.00000 58.80000 0.02400 58.82400 ;
    END
  END wdata[192]
  PIN wdata[193]
    DIRECTION INPUT ;
    USE SIGNAL ;
    PORT
      LAYER M4 ;
      RECT 0.00000 58.89600 0.02400 58.92000 ;
    END
  END wdata[193]
  PIN wdata[194]
    DIRECTION INPUT ;
    USE SIGNAL ;
    PORT
      LAYER M4 ;
      RECT 0.00000 58.99200 0.02400 59.01600 ;
    END
  END wdata[194]
  PIN wdata[195]
    DIRECTION INPUT ;
    USE SIGNAL ;
    PORT
      LAYER M4 ;
      RECT 0.00000 59.08800 0.02400 59.11200 ;
    END
  END wdata[195]
  PIN wdata[196]
    DIRECTION INPUT ;
    USE SIGNAL ;
    PORT
      LAYER M4 ;
      RECT 0.00000 59.18400 0.02400 59.20800 ;
    END
  END wdata[196]
  PIN wdata[197]
    DIRECTION INPUT ;
    USE SIGNAL ;
    PORT
      LAYER M4 ;
      RECT 0.00000 59.28000 0.02400 59.30400 ;
    END
  END wdata[197]
  PIN wdata[198]
    DIRECTION INPUT ;
    USE SIGNAL ;
    PORT
      LAYER M4 ;
      RECT 0.00000 59.37600 0.02400 59.40000 ;
    END
  END wdata[198]
  PIN wdata[199]
    DIRECTION INPUT ;
    USE SIGNAL ;
    PORT
      LAYER M4 ;
      RECT 0.00000 59.47200 0.02400 59.49600 ;
    END
  END wdata[199]
  PIN wdata[200]
    DIRECTION INPUT ;
    USE SIGNAL ;
    PORT
      LAYER M4 ;
      RECT 0.00000 59.56800 0.02400 59.59200 ;
    END
  END wdata[200]
  PIN wdata[201]
    DIRECTION INPUT ;
    USE SIGNAL ;
    PORT
      LAYER M4 ;
      RECT 0.00000 59.66400 0.02400 59.68800 ;
    END
  END wdata[201]
  PIN wdata[202]
    DIRECTION INPUT ;
    USE SIGNAL ;
    PORT
      LAYER M4 ;
      RECT 0.00000 59.76000 0.02400 59.78400 ;
    END
  END wdata[202]
  PIN wdata[203]
    DIRECTION INPUT ;
    USE SIGNAL ;
    PORT
      LAYER M4 ;
      RECT 0.00000 59.85600 0.02400 59.88000 ;
    END
  END wdata[203]
  PIN wdata[204]
    DIRECTION INPUT ;
    USE SIGNAL ;
    PORT
      LAYER M4 ;
      RECT 0.00000 59.95200 0.02400 59.97600 ;
    END
  END wdata[204]
  PIN wdata[205]
    DIRECTION INPUT ;
    USE SIGNAL ;
    PORT
      LAYER M4 ;
      RECT 0.00000 60.04800 0.02400 60.07200 ;
    END
  END wdata[205]
  PIN wdata[206]
    DIRECTION INPUT ;
    USE SIGNAL ;
    PORT
      LAYER M4 ;
      RECT 0.00000 60.14400 0.02400 60.16800 ;
    END
  END wdata[206]
  PIN wdata[207]
    DIRECTION INPUT ;
    USE SIGNAL ;
    PORT
      LAYER M4 ;
      RECT 0.00000 60.24000 0.02400 60.26400 ;
    END
  END wdata[207]
  PIN wdata[208]
    DIRECTION INPUT ;
    USE SIGNAL ;
    PORT
      LAYER M4 ;
      RECT 0.00000 60.33600 0.02400 60.36000 ;
    END
  END wdata[208]
  PIN wdata[209]
    DIRECTION INPUT ;
    USE SIGNAL ;
    PORT
      LAYER M4 ;
      RECT 0.00000 60.43200 0.02400 60.45600 ;
    END
  END wdata[209]
  PIN wdata[210]
    DIRECTION INPUT ;
    USE SIGNAL ;
    PORT
      LAYER M4 ;
      RECT 0.00000 60.52800 0.02400 60.55200 ;
    END
  END wdata[210]
  PIN wdata[211]
    DIRECTION INPUT ;
    USE SIGNAL ;
    PORT
      LAYER M4 ;
      RECT 0.00000 60.62400 0.02400 60.64800 ;
    END
  END wdata[211]
  PIN wdata[212]
    DIRECTION INPUT ;
    USE SIGNAL ;
    PORT
      LAYER M4 ;
      RECT 0.00000 60.72000 0.02400 60.74400 ;
    END
  END wdata[212]
  PIN wdata[213]
    DIRECTION INPUT ;
    USE SIGNAL ;
    PORT
      LAYER M4 ;
      RECT 0.00000 60.81600 0.02400 60.84000 ;
    END
  END wdata[213]
  PIN wdata[214]
    DIRECTION INPUT ;
    USE SIGNAL ;
    PORT
      LAYER M4 ;
      RECT 0.00000 60.91200 0.02400 60.93600 ;
    END
  END wdata[214]
  PIN wdata[215]
    DIRECTION INPUT ;
    USE SIGNAL ;
    PORT
      LAYER M4 ;
      RECT 0.00000 61.00800 0.02400 61.03200 ;
    END
  END wdata[215]
  PIN wdata[216]
    DIRECTION INPUT ;
    USE SIGNAL ;
    PORT
      LAYER M4 ;
      RECT 0.00000 61.10400 0.02400 61.12800 ;
    END
  END wdata[216]
  PIN wdata[217]
    DIRECTION INPUT ;
    USE SIGNAL ;
    PORT
      LAYER M4 ;
      RECT 0.00000 61.20000 0.02400 61.22400 ;
    END
  END wdata[217]
  PIN wdata[218]
    DIRECTION INPUT ;
    USE SIGNAL ;
    PORT
      LAYER M4 ;
      RECT 0.00000 61.29600 0.02400 61.32000 ;
    END
  END wdata[218]
  PIN wdata[219]
    DIRECTION INPUT ;
    USE SIGNAL ;
    PORT
      LAYER M4 ;
      RECT 0.00000 61.39200 0.02400 61.41600 ;
    END
  END wdata[219]
  PIN wdata[220]
    DIRECTION INPUT ;
    USE SIGNAL ;
    PORT
      LAYER M4 ;
      RECT 0.00000 61.48800 0.02400 61.51200 ;
    END
  END wdata[220]
  PIN wdata[221]
    DIRECTION INPUT ;
    USE SIGNAL ;
    PORT
      LAYER M4 ;
      RECT 0.00000 61.58400 0.02400 61.60800 ;
    END
  END wdata[221]
  PIN wdata[222]
    DIRECTION INPUT ;
    USE SIGNAL ;
    PORT
      LAYER M4 ;
      RECT 0.00000 61.68000 0.02400 61.70400 ;
    END
  END wdata[222]
  PIN wdata[223]
    DIRECTION INPUT ;
    USE SIGNAL ;
    PORT
      LAYER M4 ;
      RECT 0.00000 61.77600 0.02400 61.80000 ;
    END
  END wdata[223]
  PIN wdata[224]
    DIRECTION INPUT ;
    USE SIGNAL ;
    PORT
      LAYER M4 ;
      RECT 0.00000 61.87200 0.02400 61.89600 ;
    END
  END wdata[224]
  PIN wdata[225]
    DIRECTION INPUT ;
    USE SIGNAL ;
    PORT
      LAYER M4 ;
      RECT 0.00000 61.96800 0.02400 61.99200 ;
    END
  END wdata[225]
  PIN wdata[226]
    DIRECTION INPUT ;
    USE SIGNAL ;
    PORT
      LAYER M4 ;
      RECT 0.00000 62.06400 0.02400 62.08800 ;
    END
  END wdata[226]
  PIN wdata[227]
    DIRECTION INPUT ;
    USE SIGNAL ;
    PORT
      LAYER M4 ;
      RECT 0.00000 62.16000 0.02400 62.18400 ;
    END
  END wdata[227]
  PIN wdata[228]
    DIRECTION INPUT ;
    USE SIGNAL ;
    PORT
      LAYER M4 ;
      RECT 0.00000 62.25600 0.02400 62.28000 ;
    END
  END wdata[228]
  PIN wdata[229]
    DIRECTION INPUT ;
    USE SIGNAL ;
    PORT
      LAYER M4 ;
      RECT 0.00000 62.35200 0.02400 62.37600 ;
    END
  END wdata[229]
  PIN wdata[230]
    DIRECTION INPUT ;
    USE SIGNAL ;
    PORT
      LAYER M4 ;
      RECT 0.00000 62.44800 0.02400 62.47200 ;
    END
  END wdata[230]
  PIN wdata[231]
    DIRECTION INPUT ;
    USE SIGNAL ;
    PORT
      LAYER M4 ;
      RECT 0.00000 62.54400 0.02400 62.56800 ;
    END
  END wdata[231]
  PIN wdata[232]
    DIRECTION INPUT ;
    USE SIGNAL ;
    PORT
      LAYER M4 ;
      RECT 0.00000 62.64000 0.02400 62.66400 ;
    END
  END wdata[232]
  PIN wdata[233]
    DIRECTION INPUT ;
    USE SIGNAL ;
    PORT
      LAYER M4 ;
      RECT 0.00000 62.73600 0.02400 62.76000 ;
    END
  END wdata[233]
  PIN wdata[234]
    DIRECTION INPUT ;
    USE SIGNAL ;
    PORT
      LAYER M4 ;
      RECT 0.00000 62.83200 0.02400 62.85600 ;
    END
  END wdata[234]
  PIN wdata[235]
    DIRECTION INPUT ;
    USE SIGNAL ;
    PORT
      LAYER M4 ;
      RECT 0.00000 62.92800 0.02400 62.95200 ;
    END
  END wdata[235]
  PIN wdata[236]
    DIRECTION INPUT ;
    USE SIGNAL ;
    PORT
      LAYER M4 ;
      RECT 0.00000 63.02400 0.02400 63.04800 ;
    END
  END wdata[236]
  PIN wdata[237]
    DIRECTION INPUT ;
    USE SIGNAL ;
    PORT
      LAYER M4 ;
      RECT 0.00000 63.12000 0.02400 63.14400 ;
    END
  END wdata[237]
  PIN wdata[238]
    DIRECTION INPUT ;
    USE SIGNAL ;
    PORT
      LAYER M4 ;
      RECT 0.00000 63.21600 0.02400 63.24000 ;
    END
  END wdata[238]
  PIN wdata[239]
    DIRECTION INPUT ;
    USE SIGNAL ;
    PORT
      LAYER M4 ;
      RECT 0.00000 63.31200 0.02400 63.33600 ;
    END
  END wdata[239]
  PIN wdata[240]
    DIRECTION INPUT ;
    USE SIGNAL ;
    PORT
      LAYER M4 ;
      RECT 0.00000 63.40800 0.02400 63.43200 ;
    END
  END wdata[240]
  PIN wdata[241]
    DIRECTION INPUT ;
    USE SIGNAL ;
    PORT
      LAYER M4 ;
      RECT 0.00000 63.50400 0.02400 63.52800 ;
    END
  END wdata[241]
  PIN wdata[242]
    DIRECTION INPUT ;
    USE SIGNAL ;
    PORT
      LAYER M4 ;
      RECT 0.00000 63.60000 0.02400 63.62400 ;
    END
  END wdata[242]
  PIN wdata[243]
    DIRECTION INPUT ;
    USE SIGNAL ;
    PORT
      LAYER M4 ;
      RECT 0.00000 63.69600 0.02400 63.72000 ;
    END
  END wdata[243]
  PIN wdata[244]
    DIRECTION INPUT ;
    USE SIGNAL ;
    PORT
      LAYER M4 ;
      RECT 0.00000 63.79200 0.02400 63.81600 ;
    END
  END wdata[244]
  PIN wdata[245]
    DIRECTION INPUT ;
    USE SIGNAL ;
    PORT
      LAYER M4 ;
      RECT 0.00000 63.88800 0.02400 63.91200 ;
    END
  END wdata[245]
  PIN wdata[246]
    DIRECTION INPUT ;
    USE SIGNAL ;
    PORT
      LAYER M4 ;
      RECT 0.00000 63.98400 0.02400 64.00800 ;
    END
  END wdata[246]
  PIN wdata[247]
    DIRECTION INPUT ;
    USE SIGNAL ;
    PORT
      LAYER M4 ;
      RECT 0.00000 64.08000 0.02400 64.10400 ;
    END
  END wdata[247]
  PIN wdata[248]
    DIRECTION INPUT ;
    USE SIGNAL ;
    PORT
      LAYER M4 ;
      RECT 0.00000 64.17600 0.02400 64.20000 ;
    END
  END wdata[248]
  PIN wdata[249]
    DIRECTION INPUT ;
    USE SIGNAL ;
    PORT
      LAYER M4 ;
      RECT 0.00000 64.27200 0.02400 64.29600 ;
    END
  END wdata[249]
  PIN wdata[250]
    DIRECTION INPUT ;
    USE SIGNAL ;
    PORT
      LAYER M4 ;
      RECT 0.00000 64.36800 0.02400 64.39200 ;
    END
  END wdata[250]
  PIN wdata[251]
    DIRECTION INPUT ;
    USE SIGNAL ;
    PORT
      LAYER M4 ;
      RECT 0.00000 64.46400 0.02400 64.48800 ;
    END
  END wdata[251]
  PIN wdata[252]
    DIRECTION INPUT ;
    USE SIGNAL ;
    PORT
      LAYER M4 ;
      RECT 0.00000 64.56000 0.02400 64.58400 ;
    END
  END wdata[252]
  PIN wdata[253]
    DIRECTION INPUT ;
    USE SIGNAL ;
    PORT
      LAYER M4 ;
      RECT 0.00000 64.65600 0.02400 64.68000 ;
    END
  END wdata[253]
  PIN wdata[254]
    DIRECTION INPUT ;
    USE SIGNAL ;
    PORT
      LAYER M4 ;
      RECT 0.00000 64.75200 0.02400 64.77600 ;
    END
  END wdata[254]
  PIN wdata[255]
    DIRECTION INPUT ;
    USE SIGNAL ;
    PORT
      LAYER M4 ;
      RECT 0.00000 64.84800 0.02400 64.87200 ;
    END
  END wdata[255]
  PIN wdata[256]
    DIRECTION INPUT ;
    USE SIGNAL ;
    PORT
      LAYER M4 ;
      RECT 0.00000 64.94400 0.02400 64.96800 ;
    END
  END wdata[256]
  PIN wdata[257]
    DIRECTION INPUT ;
    USE SIGNAL ;
    PORT
      LAYER M4 ;
      RECT 0.00000 65.04000 0.02400 65.06400 ;
    END
  END wdata[257]
  PIN wdata[258]
    DIRECTION INPUT ;
    USE SIGNAL ;
    PORT
      LAYER M4 ;
      RECT 0.00000 65.13600 0.02400 65.16000 ;
    END
  END wdata[258]
  PIN wdata[259]
    DIRECTION INPUT ;
    USE SIGNAL ;
    PORT
      LAYER M4 ;
      RECT 0.00000 65.23200 0.02400 65.25600 ;
    END
  END wdata[259]
  PIN wdata[260]
    DIRECTION INPUT ;
    USE SIGNAL ;
    PORT
      LAYER M4 ;
      RECT 0.00000 65.32800 0.02400 65.35200 ;
    END
  END wdata[260]
  PIN wdata[261]
    DIRECTION INPUT ;
    USE SIGNAL ;
    PORT
      LAYER M4 ;
      RECT 0.00000 65.42400 0.02400 65.44800 ;
    END
  END wdata[261]
  PIN wdata[262]
    DIRECTION INPUT ;
    USE SIGNAL ;
    PORT
      LAYER M4 ;
      RECT 0.00000 65.52000 0.02400 65.54400 ;
    END
  END wdata[262]
  PIN wdata[263]
    DIRECTION INPUT ;
    USE SIGNAL ;
    PORT
      LAYER M4 ;
      RECT 0.00000 65.61600 0.02400 65.64000 ;
    END
  END wdata[263]
  PIN wdata[264]
    DIRECTION INPUT ;
    USE SIGNAL ;
    PORT
      LAYER M4 ;
      RECT 0.00000 65.71200 0.02400 65.73600 ;
    END
  END wdata[264]
  PIN wdata[265]
    DIRECTION INPUT ;
    USE SIGNAL ;
    PORT
      LAYER M4 ;
      RECT 0.00000 65.80800 0.02400 65.83200 ;
    END
  END wdata[265]
  PIN wdata[266]
    DIRECTION INPUT ;
    USE SIGNAL ;
    PORT
      LAYER M4 ;
      RECT 0.00000 65.90400 0.02400 65.92800 ;
    END
  END wdata[266]
  PIN wdata[267]
    DIRECTION INPUT ;
    USE SIGNAL ;
    PORT
      LAYER M4 ;
      RECT 0.00000 66.00000 0.02400 66.02400 ;
    END
  END wdata[267]
  PIN wdata[268]
    DIRECTION INPUT ;
    USE SIGNAL ;
    PORT
      LAYER M4 ;
      RECT 0.00000 66.09600 0.02400 66.12000 ;
    END
  END wdata[268]
  PIN wdata[269]
    DIRECTION INPUT ;
    USE SIGNAL ;
    PORT
      LAYER M4 ;
      RECT 0.00000 66.19200 0.02400 66.21600 ;
    END
  END wdata[269]
  PIN wdata[270]
    DIRECTION INPUT ;
    USE SIGNAL ;
    PORT
      LAYER M4 ;
      RECT 0.00000 66.28800 0.02400 66.31200 ;
    END
  END wdata[270]
  PIN wdata[271]
    DIRECTION INPUT ;
    USE SIGNAL ;
    PORT
      LAYER M4 ;
      RECT 0.00000 66.38400 0.02400 66.40800 ;
    END
  END wdata[271]
  PIN wdata[272]
    DIRECTION INPUT ;
    USE SIGNAL ;
    PORT
      LAYER M4 ;
      RECT 0.00000 66.48000 0.02400 66.50400 ;
    END
  END wdata[272]
  PIN wdata[273]
    DIRECTION INPUT ;
    USE SIGNAL ;
    PORT
      LAYER M4 ;
      RECT 0.00000 66.57600 0.02400 66.60000 ;
    END
  END wdata[273]
  PIN wdata[274]
    DIRECTION INPUT ;
    USE SIGNAL ;
    PORT
      LAYER M4 ;
      RECT 0.00000 66.67200 0.02400 66.69600 ;
    END
  END wdata[274]
  PIN wdata[275]
    DIRECTION INPUT ;
    USE SIGNAL ;
    PORT
      LAYER M4 ;
      RECT 0.00000 66.76800 0.02400 66.79200 ;
    END
  END wdata[275]
  PIN wdata[276]
    DIRECTION INPUT ;
    USE SIGNAL ;
    PORT
      LAYER M4 ;
      RECT 0.00000 66.86400 0.02400 66.88800 ;
    END
  END wdata[276]
  PIN wdata[277]
    DIRECTION INPUT ;
    USE SIGNAL ;
    PORT
      LAYER M4 ;
      RECT 0.00000 66.96000 0.02400 66.98400 ;
    END
  END wdata[277]
  PIN wdata[278]
    DIRECTION INPUT ;
    USE SIGNAL ;
    PORT
      LAYER M4 ;
      RECT 0.00000 67.05600 0.02400 67.08000 ;
    END
  END wdata[278]
  PIN wdata[279]
    DIRECTION INPUT ;
    USE SIGNAL ;
    PORT
      LAYER M4 ;
      RECT 0.00000 67.15200 0.02400 67.17600 ;
    END
  END wdata[279]
  PIN wdata[280]
    DIRECTION INPUT ;
    USE SIGNAL ;
    PORT
      LAYER M4 ;
      RECT 0.00000 67.24800 0.02400 67.27200 ;
    END
  END wdata[280]
  PIN wdata[281]
    DIRECTION INPUT ;
    USE SIGNAL ;
    PORT
      LAYER M4 ;
      RECT 0.00000 67.34400 0.02400 67.36800 ;
    END
  END wdata[281]
  PIN wdata[282]
    DIRECTION INPUT ;
    USE SIGNAL ;
    PORT
      LAYER M4 ;
      RECT 0.00000 67.44000 0.02400 67.46400 ;
    END
  END wdata[282]
  PIN wdata[283]
    DIRECTION INPUT ;
    USE SIGNAL ;
    PORT
      LAYER M4 ;
      RECT 0.00000 67.53600 0.02400 67.56000 ;
    END
  END wdata[283]
  PIN wdata[284]
    DIRECTION INPUT ;
    USE SIGNAL ;
    PORT
      LAYER M4 ;
      RECT 0.00000 67.63200 0.02400 67.65600 ;
    END
  END wdata[284]
  PIN wdata[285]
    DIRECTION INPUT ;
    USE SIGNAL ;
    PORT
      LAYER M4 ;
      RECT 0.00000 67.72800 0.02400 67.75200 ;
    END
  END wdata[285]
  PIN wdata[286]
    DIRECTION INPUT ;
    USE SIGNAL ;
    PORT
      LAYER M4 ;
      RECT 0.00000 67.82400 0.02400 67.84800 ;
    END
  END wdata[286]
  PIN wdata[287]
    DIRECTION INPUT ;
    USE SIGNAL ;
    PORT
      LAYER M4 ;
      RECT 0.00000 67.92000 0.02400 67.94400 ;
    END
  END wdata[287]
  PIN wdata[288]
    DIRECTION INPUT ;
    USE SIGNAL ;
    PORT
      LAYER M4 ;
      RECT 0.00000 68.01600 0.02400 68.04000 ;
    END
  END wdata[288]
  PIN wdata[289]
    DIRECTION INPUT ;
    USE SIGNAL ;
    PORT
      LAYER M4 ;
      RECT 0.00000 68.11200 0.02400 68.13600 ;
    END
  END wdata[289]
  PIN wdata[290]
    DIRECTION INPUT ;
    USE SIGNAL ;
    PORT
      LAYER M4 ;
      RECT 0.00000 68.20800 0.02400 68.23200 ;
    END
  END wdata[290]
  PIN wdata[291]
    DIRECTION INPUT ;
    USE SIGNAL ;
    PORT
      LAYER M4 ;
      RECT 0.00000 68.30400 0.02400 68.32800 ;
    END
  END wdata[291]
  PIN wdata[292]
    DIRECTION INPUT ;
    USE SIGNAL ;
    PORT
      LAYER M4 ;
      RECT 0.00000 68.40000 0.02400 68.42400 ;
    END
  END wdata[292]
  PIN wdata[293]
    DIRECTION INPUT ;
    USE SIGNAL ;
    PORT
      LAYER M4 ;
      RECT 0.00000 68.49600 0.02400 68.52000 ;
    END
  END wdata[293]
  PIN wdata[294]
    DIRECTION INPUT ;
    USE SIGNAL ;
    PORT
      LAYER M4 ;
      RECT 0.00000 68.59200 0.02400 68.61600 ;
    END
  END wdata[294]
  PIN wdata[295]
    DIRECTION INPUT ;
    USE SIGNAL ;
    PORT
      LAYER M4 ;
      RECT 0.00000 68.68800 0.02400 68.71200 ;
    END
  END wdata[295]
  PIN wdata[296]
    DIRECTION INPUT ;
    USE SIGNAL ;
    PORT
      LAYER M4 ;
      RECT 0.00000 68.78400 0.02400 68.80800 ;
    END
  END wdata[296]
  PIN wdata[297]
    DIRECTION INPUT ;
    USE SIGNAL ;
    PORT
      LAYER M4 ;
      RECT 0.00000 68.88000 0.02400 68.90400 ;
    END
  END wdata[297]
  PIN wdata[298]
    DIRECTION INPUT ;
    USE SIGNAL ;
    PORT
      LAYER M4 ;
      RECT 0.00000 68.97600 0.02400 69.00000 ;
    END
  END wdata[298]
  PIN wdata[299]
    DIRECTION INPUT ;
    USE SIGNAL ;
    PORT
      LAYER M4 ;
      RECT 0.00000 69.07200 0.02400 69.09600 ;
    END
  END wdata[299]
  PIN wdata[300]
    DIRECTION INPUT ;
    USE SIGNAL ;
    PORT
      LAYER M4 ;
      RECT 0.00000 69.16800 0.02400 69.19200 ;
    END
  END wdata[300]
  PIN wdata[301]
    DIRECTION INPUT ;
    USE SIGNAL ;
    PORT
      LAYER M4 ;
      RECT 0.00000 69.26400 0.02400 69.28800 ;
    END
  END wdata[301]
  PIN wdata[302]
    DIRECTION INPUT ;
    USE SIGNAL ;
    PORT
      LAYER M4 ;
      RECT 0.00000 69.36000 0.02400 69.38400 ;
    END
  END wdata[302]
  PIN wdata[303]
    DIRECTION INPUT ;
    USE SIGNAL ;
    PORT
      LAYER M4 ;
      RECT 0.00000 69.45600 0.02400 69.48000 ;
    END
  END wdata[303]
  PIN wdata[304]
    DIRECTION INPUT ;
    USE SIGNAL ;
    PORT
      LAYER M4 ;
      RECT 0.00000 69.55200 0.02400 69.57600 ;
    END
  END wdata[304]
  PIN wdata[305]
    DIRECTION INPUT ;
    USE SIGNAL ;
    PORT
      LAYER M4 ;
      RECT 0.00000 69.64800 0.02400 69.67200 ;
    END
  END wdata[305]
  PIN wdata[306]
    DIRECTION INPUT ;
    USE SIGNAL ;
    PORT
      LAYER M4 ;
      RECT 0.00000 69.74400 0.02400 69.76800 ;
    END
  END wdata[306]
  PIN wdata[307]
    DIRECTION INPUT ;
    USE SIGNAL ;
    PORT
      LAYER M4 ;
      RECT 0.00000 69.84000 0.02400 69.86400 ;
    END
  END wdata[307]
  PIN wdata[308]
    DIRECTION INPUT ;
    USE SIGNAL ;
    PORT
      LAYER M4 ;
      RECT 0.00000 69.93600 0.02400 69.96000 ;
    END
  END wdata[308]
  PIN wdata[309]
    DIRECTION INPUT ;
    USE SIGNAL ;
    PORT
      LAYER M4 ;
      RECT 0.00000 70.03200 0.02400 70.05600 ;
    END
  END wdata[309]
  PIN wdata[310]
    DIRECTION INPUT ;
    USE SIGNAL ;
    PORT
      LAYER M4 ;
      RECT 0.00000 70.12800 0.02400 70.15200 ;
    END
  END wdata[310]
  PIN wdata[311]
    DIRECTION INPUT ;
    USE SIGNAL ;
    PORT
      LAYER M4 ;
      RECT 0.00000 70.22400 0.02400 70.24800 ;
    END
  END wdata[311]
  PIN wdata[312]
    DIRECTION INPUT ;
    USE SIGNAL ;
    PORT
      LAYER M4 ;
      RECT 0.00000 70.32000 0.02400 70.34400 ;
    END
  END wdata[312]
  PIN wdata[313]
    DIRECTION INPUT ;
    USE SIGNAL ;
    PORT
      LAYER M4 ;
      RECT 0.00000 70.41600 0.02400 70.44000 ;
    END
  END wdata[313]
  PIN wdata[314]
    DIRECTION INPUT ;
    USE SIGNAL ;
    PORT
      LAYER M4 ;
      RECT 0.00000 70.51200 0.02400 70.53600 ;
    END
  END wdata[314]
  PIN wdata[315]
    DIRECTION INPUT ;
    USE SIGNAL ;
    PORT
      LAYER M4 ;
      RECT 0.00000 70.60800 0.02400 70.63200 ;
    END
  END wdata[315]
  PIN wdata[316]
    DIRECTION INPUT ;
    USE SIGNAL ;
    PORT
      LAYER M4 ;
      RECT 0.00000 70.70400 0.02400 70.72800 ;
    END
  END wdata[316]
  PIN wdata[317]
    DIRECTION INPUT ;
    USE SIGNAL ;
    PORT
      LAYER M4 ;
      RECT 0.00000 70.80000 0.02400 70.82400 ;
    END
  END wdata[317]
  PIN wdata[318]
    DIRECTION INPUT ;
    USE SIGNAL ;
    PORT
      LAYER M4 ;
      RECT 0.00000 70.89600 0.02400 70.92000 ;
    END
  END wdata[318]
  PIN wdata[319]
    DIRECTION INPUT ;
    USE SIGNAL ;
    PORT
      LAYER M4 ;
      RECT 0.00000 70.99200 0.02400 71.01600 ;
    END
  END wdata[319]
  PIN wdata[320]
    DIRECTION INPUT ;
    USE SIGNAL ;
    PORT
      LAYER M4 ;
      RECT 0.00000 71.08800 0.02400 71.11200 ;
    END
  END wdata[320]
  PIN wdata[321]
    DIRECTION INPUT ;
    USE SIGNAL ;
    PORT
      LAYER M4 ;
      RECT 0.00000 71.18400 0.02400 71.20800 ;
    END
  END wdata[321]
  PIN wdata[322]
    DIRECTION INPUT ;
    USE SIGNAL ;
    PORT
      LAYER M4 ;
      RECT 0.00000 71.28000 0.02400 71.30400 ;
    END
  END wdata[322]
  PIN wdata[323]
    DIRECTION INPUT ;
    USE SIGNAL ;
    PORT
      LAYER M4 ;
      RECT 0.00000 71.37600 0.02400 71.40000 ;
    END
  END wdata[323]
  PIN wdata[324]
    DIRECTION INPUT ;
    USE SIGNAL ;
    PORT
      LAYER M4 ;
      RECT 0.00000 71.47200 0.02400 71.49600 ;
    END
  END wdata[324]
  PIN wdata[325]
    DIRECTION INPUT ;
    USE SIGNAL ;
    PORT
      LAYER M4 ;
      RECT 0.00000 71.56800 0.02400 71.59200 ;
    END
  END wdata[325]
  PIN wdata[326]
    DIRECTION INPUT ;
    USE SIGNAL ;
    PORT
      LAYER M4 ;
      RECT 0.00000 71.66400 0.02400 71.68800 ;
    END
  END wdata[326]
  PIN wdata[327]
    DIRECTION INPUT ;
    USE SIGNAL ;
    PORT
      LAYER M4 ;
      RECT 0.00000 71.76000 0.02400 71.78400 ;
    END
  END wdata[327]
  PIN wdata[328]
    DIRECTION INPUT ;
    USE SIGNAL ;
    PORT
      LAYER M4 ;
      RECT 0.00000 71.85600 0.02400 71.88000 ;
    END
  END wdata[328]
  PIN wdata[329]
    DIRECTION INPUT ;
    USE SIGNAL ;
    PORT
      LAYER M4 ;
      RECT 0.00000 71.95200 0.02400 71.97600 ;
    END
  END wdata[329]
  PIN wdata[330]
    DIRECTION INPUT ;
    USE SIGNAL ;
    PORT
      LAYER M4 ;
      RECT 0.00000 72.04800 0.02400 72.07200 ;
    END
  END wdata[330]
  PIN wdata[331]
    DIRECTION INPUT ;
    USE SIGNAL ;
    PORT
      LAYER M4 ;
      RECT 0.00000 72.14400 0.02400 72.16800 ;
    END
  END wdata[331]
  PIN wdata[332]
    DIRECTION INPUT ;
    USE SIGNAL ;
    PORT
      LAYER M4 ;
      RECT 0.00000 72.24000 0.02400 72.26400 ;
    END
  END wdata[332]
  PIN wdata[333]
    DIRECTION INPUT ;
    USE SIGNAL ;
    PORT
      LAYER M4 ;
      RECT 0.00000 72.33600 0.02400 72.36000 ;
    END
  END wdata[333]
  PIN wdata[334]
    DIRECTION INPUT ;
    USE SIGNAL ;
    PORT
      LAYER M4 ;
      RECT 0.00000 72.43200 0.02400 72.45600 ;
    END
  END wdata[334]
  PIN wdata[335]
    DIRECTION INPUT ;
    USE SIGNAL ;
    PORT
      LAYER M4 ;
      RECT 0.00000 72.52800 0.02400 72.55200 ;
    END
  END wdata[335]
  PIN wdata[336]
    DIRECTION INPUT ;
    USE SIGNAL ;
    PORT
      LAYER M4 ;
      RECT 0.00000 72.62400 0.02400 72.64800 ;
    END
  END wdata[336]
  PIN wdata[337]
    DIRECTION INPUT ;
    USE SIGNAL ;
    PORT
      LAYER M4 ;
      RECT 0.00000 72.72000 0.02400 72.74400 ;
    END
  END wdata[337]
  PIN wdata[338]
    DIRECTION INPUT ;
    USE SIGNAL ;
    PORT
      LAYER M4 ;
      RECT 0.00000 72.81600 0.02400 72.84000 ;
    END
  END wdata[338]
  PIN wdata[339]
    DIRECTION INPUT ;
    USE SIGNAL ;
    PORT
      LAYER M4 ;
      RECT 0.00000 72.91200 0.02400 72.93600 ;
    END
  END wdata[339]
  PIN wdata[340]
    DIRECTION INPUT ;
    USE SIGNAL ;
    PORT
      LAYER M4 ;
      RECT 0.00000 73.00800 0.02400 73.03200 ;
    END
  END wdata[340]
  PIN wdata[341]
    DIRECTION INPUT ;
    USE SIGNAL ;
    PORT
      LAYER M4 ;
      RECT 0.00000 73.10400 0.02400 73.12800 ;
    END
  END wdata[341]
  PIN wdata[342]
    DIRECTION INPUT ;
    USE SIGNAL ;
    PORT
      LAYER M4 ;
      RECT 0.00000 73.20000 0.02400 73.22400 ;
    END
  END wdata[342]
  PIN wdata[343]
    DIRECTION INPUT ;
    USE SIGNAL ;
    PORT
      LAYER M4 ;
      RECT 0.00000 73.29600 0.02400 73.32000 ;
    END
  END wdata[343]
  PIN wdata[344]
    DIRECTION INPUT ;
    USE SIGNAL ;
    PORT
      LAYER M4 ;
      RECT 0.00000 73.39200 0.02400 73.41600 ;
    END
  END wdata[344]
  PIN wdata[345]
    DIRECTION INPUT ;
    USE SIGNAL ;
    PORT
      LAYER M4 ;
      RECT 0.00000 73.48800 0.02400 73.51200 ;
    END
  END wdata[345]
  PIN wdata[346]
    DIRECTION INPUT ;
    USE SIGNAL ;
    PORT
      LAYER M4 ;
      RECT 0.00000 73.58400 0.02400 73.60800 ;
    END
  END wdata[346]
  PIN wdata[347]
    DIRECTION INPUT ;
    USE SIGNAL ;
    PORT
      LAYER M4 ;
      RECT 0.00000 73.68000 0.02400 73.70400 ;
    END
  END wdata[347]
  PIN wdata[348]
    DIRECTION INPUT ;
    USE SIGNAL ;
    PORT
      LAYER M4 ;
      RECT 0.00000 73.77600 0.02400 73.80000 ;
    END
  END wdata[348]
  PIN wdata[349]
    DIRECTION INPUT ;
    USE SIGNAL ;
    PORT
      LAYER M4 ;
      RECT 0.00000 73.87200 0.02400 73.89600 ;
    END
  END wdata[349]
  PIN wdata[350]
    DIRECTION INPUT ;
    USE SIGNAL ;
    PORT
      LAYER M4 ;
      RECT 0.00000 73.96800 0.02400 73.99200 ;
    END
  END wdata[350]
  PIN wdata[351]
    DIRECTION INPUT ;
    USE SIGNAL ;
    PORT
      LAYER M4 ;
      RECT 0.00000 74.06400 0.02400 74.08800 ;
    END
  END wdata[351]
  PIN wdata[352]
    DIRECTION INPUT ;
    USE SIGNAL ;
    PORT
      LAYER M4 ;
      RECT 0.00000 74.16000 0.02400 74.18400 ;
    END
  END wdata[352]
  PIN wdata[353]
    DIRECTION INPUT ;
    USE SIGNAL ;
    PORT
      LAYER M4 ;
      RECT 0.00000 74.25600 0.02400 74.28000 ;
    END
  END wdata[353]
  PIN wdata[354]
    DIRECTION INPUT ;
    USE SIGNAL ;
    PORT
      LAYER M4 ;
      RECT 0.00000 74.35200 0.02400 74.37600 ;
    END
  END wdata[354]
  PIN wdata[355]
    DIRECTION INPUT ;
    USE SIGNAL ;
    PORT
      LAYER M4 ;
      RECT 0.00000 74.44800 0.02400 74.47200 ;
    END
  END wdata[355]
  PIN wdata[356]
    DIRECTION INPUT ;
    USE SIGNAL ;
    PORT
      LAYER M4 ;
      RECT 0.00000 74.54400 0.02400 74.56800 ;
    END
  END wdata[356]
  PIN wdata[357]
    DIRECTION INPUT ;
    USE SIGNAL ;
    PORT
      LAYER M4 ;
      RECT 0.00000 74.64000 0.02400 74.66400 ;
    END
  END wdata[357]
  PIN wdata[358]
    DIRECTION INPUT ;
    USE SIGNAL ;
    PORT
      LAYER M4 ;
      RECT 0.00000 74.73600 0.02400 74.76000 ;
    END
  END wdata[358]
  PIN wdata[359]
    DIRECTION INPUT ;
    USE SIGNAL ;
    PORT
      LAYER M4 ;
      RECT 0.00000 74.83200 0.02400 74.85600 ;
    END
  END wdata[359]
  PIN wdata[360]
    DIRECTION INPUT ;
    USE SIGNAL ;
    PORT
      LAYER M4 ;
      RECT 0.00000 74.92800 0.02400 74.95200 ;
    END
  END wdata[360]
  PIN wdata[361]
    DIRECTION INPUT ;
    USE SIGNAL ;
    PORT
      LAYER M4 ;
      RECT 0.00000 75.02400 0.02400 75.04800 ;
    END
  END wdata[361]
  PIN wdata[362]
    DIRECTION INPUT ;
    USE SIGNAL ;
    PORT
      LAYER M4 ;
      RECT 0.00000 75.12000 0.02400 75.14400 ;
    END
  END wdata[362]
  PIN wdata[363]
    DIRECTION INPUT ;
    USE SIGNAL ;
    PORT
      LAYER M4 ;
      RECT 0.00000 75.21600 0.02400 75.24000 ;
    END
  END wdata[363]
  PIN wdata[364]
    DIRECTION INPUT ;
    USE SIGNAL ;
    PORT
      LAYER M4 ;
      RECT 0.00000 75.31200 0.02400 75.33600 ;
    END
  END wdata[364]
  PIN wdata[365]
    DIRECTION INPUT ;
    USE SIGNAL ;
    PORT
      LAYER M4 ;
      RECT 0.00000 75.40800 0.02400 75.43200 ;
    END
  END wdata[365]
  PIN wdata[366]
    DIRECTION INPUT ;
    USE SIGNAL ;
    PORT
      LAYER M4 ;
      RECT 0.00000 75.50400 0.02400 75.52800 ;
    END
  END wdata[366]
  PIN wdata[367]
    DIRECTION INPUT ;
    USE SIGNAL ;
    PORT
      LAYER M4 ;
      RECT 0.00000 75.60000 0.02400 75.62400 ;
    END
  END wdata[367]
  PIN wdata[368]
    DIRECTION INPUT ;
    USE SIGNAL ;
    PORT
      LAYER M4 ;
      RECT 0.00000 75.69600 0.02400 75.72000 ;
    END
  END wdata[368]
  PIN wdata[369]
    DIRECTION INPUT ;
    USE SIGNAL ;
    PORT
      LAYER M4 ;
      RECT 0.00000 75.79200 0.02400 75.81600 ;
    END
  END wdata[369]
  PIN wdata[370]
    DIRECTION INPUT ;
    USE SIGNAL ;
    PORT
      LAYER M4 ;
      RECT 0.00000 75.88800 0.02400 75.91200 ;
    END
  END wdata[370]
  PIN wdata[371]
    DIRECTION INPUT ;
    USE SIGNAL ;
    PORT
      LAYER M4 ;
      RECT 0.00000 75.98400 0.02400 76.00800 ;
    END
  END wdata[371]
  PIN wdata[372]
    DIRECTION INPUT ;
    USE SIGNAL ;
    PORT
      LAYER M4 ;
      RECT 0.00000 76.08000 0.02400 76.10400 ;
    END
  END wdata[372]
  PIN wdata[373]
    DIRECTION INPUT ;
    USE SIGNAL ;
    PORT
      LAYER M4 ;
      RECT 0.00000 76.17600 0.02400 76.20000 ;
    END
  END wdata[373]
  PIN wdata[374]
    DIRECTION INPUT ;
    USE SIGNAL ;
    PORT
      LAYER M4 ;
      RECT 0.00000 76.27200 0.02400 76.29600 ;
    END
  END wdata[374]
  PIN wdata[375]
    DIRECTION INPUT ;
    USE SIGNAL ;
    PORT
      LAYER M4 ;
      RECT 0.00000 76.36800 0.02400 76.39200 ;
    END
  END wdata[375]
  PIN wdata[376]
    DIRECTION INPUT ;
    USE SIGNAL ;
    PORT
      LAYER M4 ;
      RECT 0.00000 76.46400 0.02400 76.48800 ;
    END
  END wdata[376]
  PIN wdata[377]
    DIRECTION INPUT ;
    USE SIGNAL ;
    PORT
      LAYER M4 ;
      RECT 0.00000 76.56000 0.02400 76.58400 ;
    END
  END wdata[377]
  PIN wdata[378]
    DIRECTION INPUT ;
    USE SIGNAL ;
    PORT
      LAYER M4 ;
      RECT 0.00000 76.65600 0.02400 76.68000 ;
    END
  END wdata[378]
  PIN wdata[379]
    DIRECTION INPUT ;
    USE SIGNAL ;
    PORT
      LAYER M4 ;
      RECT 0.00000 76.75200 0.02400 76.77600 ;
    END
  END wdata[379]
  PIN wdata[380]
    DIRECTION INPUT ;
    USE SIGNAL ;
    PORT
      LAYER M4 ;
      RECT 0.00000 76.84800 0.02400 76.87200 ;
    END
  END wdata[380]
  PIN wdata[381]
    DIRECTION INPUT ;
    USE SIGNAL ;
    PORT
      LAYER M4 ;
      RECT 0.00000 76.94400 0.02400 76.96800 ;
    END
  END wdata[381]
  PIN wdata[382]
    DIRECTION INPUT ;
    USE SIGNAL ;
    PORT
      LAYER M4 ;
      RECT 0.00000 77.04000 0.02400 77.06400 ;
    END
  END wdata[382]
  PIN wdata[383]
    DIRECTION INPUT ;
    USE SIGNAL ;
    PORT
      LAYER M4 ;
      RECT 0.00000 77.13600 0.02400 77.16000 ;
    END
  END wdata[383]
  PIN wdata[384]
    DIRECTION INPUT ;
    USE SIGNAL ;
    PORT
      LAYER M4 ;
      RECT 0.00000 77.23200 0.02400 77.25600 ;
    END
  END wdata[384]
  PIN wdata[385]
    DIRECTION INPUT ;
    USE SIGNAL ;
    PORT
      LAYER M4 ;
      RECT 0.00000 77.32800 0.02400 77.35200 ;
    END
  END wdata[385]
  PIN wdata[386]
    DIRECTION INPUT ;
    USE SIGNAL ;
    PORT
      LAYER M4 ;
      RECT 0.00000 77.42400 0.02400 77.44800 ;
    END
  END wdata[386]
  PIN wdata[387]
    DIRECTION INPUT ;
    USE SIGNAL ;
    PORT
      LAYER M4 ;
      RECT 0.00000 77.52000 0.02400 77.54400 ;
    END
  END wdata[387]
  PIN wdata[388]
    DIRECTION INPUT ;
    USE SIGNAL ;
    PORT
      LAYER M4 ;
      RECT 0.00000 77.61600 0.02400 77.64000 ;
    END
  END wdata[388]
  PIN wdata[389]
    DIRECTION INPUT ;
    USE SIGNAL ;
    PORT
      LAYER M4 ;
      RECT 0.00000 77.71200 0.02400 77.73600 ;
    END
  END wdata[389]
  PIN waddr[0]
    DIRECTION INPUT ;
    USE SIGNAL ;
    PORT
      LAYER M4 ;
      RECT 0.00000 79.92000 0.02400 79.94400 ;
    END
  END waddr[0]
  PIN waddr[1]
    DIRECTION INPUT ;
    USE SIGNAL ;
    PORT
      LAYER M4 ;
      RECT 0.00000 80.01600 0.02400 80.04000 ;
    END
  END waddr[1]
  PIN waddr[2]
    DIRECTION INPUT ;
    USE SIGNAL ;
    PORT
      LAYER M4 ;
      RECT 0.00000 80.11200 0.02400 80.13600 ;
    END
  END waddr[2]
  PIN waddr[3]
    DIRECTION INPUT ;
    USE SIGNAL ;
    PORT
      LAYER M4 ;
      RECT 0.00000 80.20800 0.02400 80.23200 ;
    END
  END waddr[3]
  PIN waddr[4]
    DIRECTION INPUT ;
    USE SIGNAL ;
    PORT
      LAYER M4 ;
      RECT 0.00000 80.30400 0.02400 80.32800 ;
    END
  END waddr[4]
  PIN waddr[5]
    DIRECTION INPUT ;
    USE SIGNAL ;
    PORT
      LAYER M4 ;
      RECT 0.00000 80.40000 0.02400 80.42400 ;
    END
  END waddr[5]
  PIN waddr[6]
    DIRECTION INPUT ;
    USE SIGNAL ;
    PORT
      LAYER M4 ;
      RECT 0.00000 80.49600 0.02400 80.52000 ;
    END
  END waddr[6]
  PIN waddr[7]
    DIRECTION INPUT ;
    USE SIGNAL ;
    PORT
      LAYER M4 ;
      RECT 0.00000 80.59200 0.02400 80.61600 ;
    END
  END waddr[7]
  PIN rb_data[0]
    DIRECTION OUTPUT ;
    USE SIGNAL ;
    PORT
      LAYER M4 ;
      RECT 0.00000 0.04800 0.02400 0.07200 ;
    END
  END rb_data[0]
  PIN rb_data[1]
    DIRECTION OUTPUT ;
    USE SIGNAL ;
    PORT
      LAYER M4 ;
      RECT 0.00000 0.14400 0.02400 0.16800 ;
    END
  END rb_data[1]
  PIN rb_data[2]
    DIRECTION OUTPUT ;
    USE SIGNAL ;
    PORT
      LAYER M4 ;
      RECT 0.00000 0.24000 0.02400 0.26400 ;
    END
  END rb_data[2]
  PIN rb_data[3]
    DIRECTION OUTPUT ;
    USE SIGNAL ;
    PORT
      LAYER M4 ;
      RECT 0.00000 0.33600 0.02400 0.36000 ;
    END
  END rb_data[3]
  PIN rb_data[4]
    DIRECTION OUTPUT ;
    USE SIGNAL ;
    PORT
      LAYER M4 ;
      RECT 0.00000 0.43200 0.02400 0.45600 ;
    END
  END rb_data[4]
  PIN rb_data[5]
    DIRECTION OUTPUT ;
    USE SIGNAL ;
    PORT
      LAYER M4 ;
      RECT 0.00000 0.52800 0.02400 0.55200 ;
    END
  END rb_data[5]
  PIN rb_data[6]
    DIRECTION OUTPUT ;
    USE SIGNAL ;
    PORT
      LAYER M4 ;
      RECT 0.00000 0.62400 0.02400 0.64800 ;
    END
  END rb_data[6]
  PIN rb_data[7]
    DIRECTION OUTPUT ;
    USE SIGNAL ;
    PORT
      LAYER M4 ;
      RECT 0.00000 0.72000 0.02400 0.74400 ;
    END
  END rb_data[7]
  PIN rb_data[8]
    DIRECTION OUTPUT ;
    USE SIGNAL ;
    PORT
      LAYER M4 ;
      RECT 0.00000 0.81600 0.02400 0.84000 ;
    END
  END rb_data[8]
  PIN rb_data[9]
    DIRECTION OUTPUT ;
    USE SIGNAL ;
    PORT
      LAYER M4 ;
      RECT 0.00000 0.91200 0.02400 0.93600 ;
    END
  END rb_data[9]
  PIN rb_data[10]
    DIRECTION OUTPUT ;
    USE SIGNAL ;
    PORT
      LAYER M4 ;
      RECT 0.00000 1.00800 0.02400 1.03200 ;
    END
  END rb_data[10]
  PIN rb_data[11]
    DIRECTION OUTPUT ;
    USE SIGNAL ;
    PORT
      LAYER M4 ;
      RECT 0.00000 1.10400 0.02400 1.12800 ;
    END
  END rb_data[11]
  PIN rb_data[12]
    DIRECTION OUTPUT ;
    USE SIGNAL ;
    PORT
      LAYER M4 ;
      RECT 0.00000 1.20000 0.02400 1.22400 ;
    END
  END rb_data[12]
  PIN rb_data[13]
    DIRECTION OUTPUT ;
    USE SIGNAL ;
    PORT
      LAYER M4 ;
      RECT 0.00000 1.29600 0.02400 1.32000 ;
    END
  END rb_data[13]
  PIN rb_data[14]
    DIRECTION OUTPUT ;
    USE SIGNAL ;
    PORT
      LAYER M4 ;
      RECT 0.00000 1.39200 0.02400 1.41600 ;
    END
  END rb_data[14]
  PIN rb_data[15]
    DIRECTION OUTPUT ;
    USE SIGNAL ;
    PORT
      LAYER M4 ;
      RECT 0.00000 1.48800 0.02400 1.51200 ;
    END
  END rb_data[15]
  PIN rb_data[16]
    DIRECTION OUTPUT ;
    USE SIGNAL ;
    PORT
      LAYER M4 ;
      RECT 0.00000 1.58400 0.02400 1.60800 ;
    END
  END rb_data[16]
  PIN rb_data[17]
    DIRECTION OUTPUT ;
    USE SIGNAL ;
    PORT
      LAYER M4 ;
      RECT 0.00000 1.68000 0.02400 1.70400 ;
    END
  END rb_data[17]
  PIN rb_data[18]
    DIRECTION OUTPUT ;
    USE SIGNAL ;
    PORT
      LAYER M4 ;
      RECT 0.00000 1.77600 0.02400 1.80000 ;
    END
  END rb_data[18]
  PIN rb_data[19]
    DIRECTION OUTPUT ;
    USE SIGNAL ;
    PORT
      LAYER M4 ;
      RECT 0.00000 1.87200 0.02400 1.89600 ;
    END
  END rb_data[19]
  PIN rb_data[20]
    DIRECTION OUTPUT ;
    USE SIGNAL ;
    PORT
      LAYER M4 ;
      RECT 0.00000 1.96800 0.02400 1.99200 ;
    END
  END rb_data[20]
  PIN rb_data[21]
    DIRECTION OUTPUT ;
    USE SIGNAL ;
    PORT
      LAYER M4 ;
      RECT 0.00000 2.06400 0.02400 2.08800 ;
    END
  END rb_data[21]
  PIN rb_data[22]
    DIRECTION OUTPUT ;
    USE SIGNAL ;
    PORT
      LAYER M4 ;
      RECT 0.00000 2.16000 0.02400 2.18400 ;
    END
  END rb_data[22]
  PIN rb_data[23]
    DIRECTION OUTPUT ;
    USE SIGNAL ;
    PORT
      LAYER M4 ;
      RECT 0.00000 2.25600 0.02400 2.28000 ;
    END
  END rb_data[23]
  PIN rb_data[24]
    DIRECTION OUTPUT ;
    USE SIGNAL ;
    PORT
      LAYER M4 ;
      RECT 0.00000 2.35200 0.02400 2.37600 ;
    END
  END rb_data[24]
  PIN rb_data[25]
    DIRECTION OUTPUT ;
    USE SIGNAL ;
    PORT
      LAYER M4 ;
      RECT 0.00000 2.44800 0.02400 2.47200 ;
    END
  END rb_data[25]
  PIN rb_data[26]
    DIRECTION OUTPUT ;
    USE SIGNAL ;
    PORT
      LAYER M4 ;
      RECT 0.00000 2.54400 0.02400 2.56800 ;
    END
  END rb_data[26]
  PIN rb_data[27]
    DIRECTION OUTPUT ;
    USE SIGNAL ;
    PORT
      LAYER M4 ;
      RECT 0.00000 2.64000 0.02400 2.66400 ;
    END
  END rb_data[27]
  PIN rb_data[28]
    DIRECTION OUTPUT ;
    USE SIGNAL ;
    PORT
      LAYER M4 ;
      RECT 0.00000 2.73600 0.02400 2.76000 ;
    END
  END rb_data[28]
  PIN rb_data[29]
    DIRECTION OUTPUT ;
    USE SIGNAL ;
    PORT
      LAYER M4 ;
      RECT 0.00000 2.83200 0.02400 2.85600 ;
    END
  END rb_data[29]
  PIN rb_data[30]
    DIRECTION OUTPUT ;
    USE SIGNAL ;
    PORT
      LAYER M4 ;
      RECT 0.00000 2.92800 0.02400 2.95200 ;
    END
  END rb_data[30]
  PIN rb_data[31]
    DIRECTION OUTPUT ;
    USE SIGNAL ;
    PORT
      LAYER M4 ;
      RECT 0.00000 3.02400 0.02400 3.04800 ;
    END
  END rb_data[31]
  PIN rb_data[32]
    DIRECTION OUTPUT ;
    USE SIGNAL ;
    PORT
      LAYER M4 ;
      RECT 0.00000 3.12000 0.02400 3.14400 ;
    END
  END rb_data[32]
  PIN rb_data[33]
    DIRECTION OUTPUT ;
    USE SIGNAL ;
    PORT
      LAYER M4 ;
      RECT 0.00000 3.21600 0.02400 3.24000 ;
    END
  END rb_data[33]
  PIN rb_data[34]
    DIRECTION OUTPUT ;
    USE SIGNAL ;
    PORT
      LAYER M4 ;
      RECT 0.00000 3.31200 0.02400 3.33600 ;
    END
  END rb_data[34]
  PIN rb_data[35]
    DIRECTION OUTPUT ;
    USE SIGNAL ;
    PORT
      LAYER M4 ;
      RECT 0.00000 3.40800 0.02400 3.43200 ;
    END
  END rb_data[35]
  PIN rb_data[36]
    DIRECTION OUTPUT ;
    USE SIGNAL ;
    PORT
      LAYER M4 ;
      RECT 0.00000 3.50400 0.02400 3.52800 ;
    END
  END rb_data[36]
  PIN rb_data[37]
    DIRECTION OUTPUT ;
    USE SIGNAL ;
    PORT
      LAYER M4 ;
      RECT 0.00000 3.60000 0.02400 3.62400 ;
    END
  END rb_data[37]
  PIN rb_data[38]
    DIRECTION OUTPUT ;
    USE SIGNAL ;
    PORT
      LAYER M4 ;
      RECT 0.00000 3.69600 0.02400 3.72000 ;
    END
  END rb_data[38]
  PIN rb_data[39]
    DIRECTION OUTPUT ;
    USE SIGNAL ;
    PORT
      LAYER M4 ;
      RECT 0.00000 3.79200 0.02400 3.81600 ;
    END
  END rb_data[39]
  PIN rb_data[40]
    DIRECTION OUTPUT ;
    USE SIGNAL ;
    PORT
      LAYER M4 ;
      RECT 0.00000 3.88800 0.02400 3.91200 ;
    END
  END rb_data[40]
  PIN rb_data[41]
    DIRECTION OUTPUT ;
    USE SIGNAL ;
    PORT
      LAYER M4 ;
      RECT 0.00000 3.98400 0.02400 4.00800 ;
    END
  END rb_data[41]
  PIN rb_data[42]
    DIRECTION OUTPUT ;
    USE SIGNAL ;
    PORT
      LAYER M4 ;
      RECT 0.00000 4.08000 0.02400 4.10400 ;
    END
  END rb_data[42]
  PIN rb_data[43]
    DIRECTION OUTPUT ;
    USE SIGNAL ;
    PORT
      LAYER M4 ;
      RECT 0.00000 4.17600 0.02400 4.20000 ;
    END
  END rb_data[43]
  PIN rb_data[44]
    DIRECTION OUTPUT ;
    USE SIGNAL ;
    PORT
      LAYER M4 ;
      RECT 0.00000 4.27200 0.02400 4.29600 ;
    END
  END rb_data[44]
  PIN rb_data[45]
    DIRECTION OUTPUT ;
    USE SIGNAL ;
    PORT
      LAYER M4 ;
      RECT 0.00000 4.36800 0.02400 4.39200 ;
    END
  END rb_data[45]
  PIN rb_data[46]
    DIRECTION OUTPUT ;
    USE SIGNAL ;
    PORT
      LAYER M4 ;
      RECT 0.00000 4.46400 0.02400 4.48800 ;
    END
  END rb_data[46]
  PIN rb_data[47]
    DIRECTION OUTPUT ;
    USE SIGNAL ;
    PORT
      LAYER M4 ;
      RECT 0.00000 4.56000 0.02400 4.58400 ;
    END
  END rb_data[47]
  PIN rb_data[48]
    DIRECTION OUTPUT ;
    USE SIGNAL ;
    PORT
      LAYER M4 ;
      RECT 0.00000 4.65600 0.02400 4.68000 ;
    END
  END rb_data[48]
  PIN rb_data[49]
    DIRECTION OUTPUT ;
    USE SIGNAL ;
    PORT
      LAYER M4 ;
      RECT 0.00000 4.75200 0.02400 4.77600 ;
    END
  END rb_data[49]
  PIN rb_data[50]
    DIRECTION OUTPUT ;
    USE SIGNAL ;
    PORT
      LAYER M4 ;
      RECT 0.00000 4.84800 0.02400 4.87200 ;
    END
  END rb_data[50]
  PIN rb_data[51]
    DIRECTION OUTPUT ;
    USE SIGNAL ;
    PORT
      LAYER M4 ;
      RECT 0.00000 4.94400 0.02400 4.96800 ;
    END
  END rb_data[51]
  PIN rb_data[52]
    DIRECTION OUTPUT ;
    USE SIGNAL ;
    PORT
      LAYER M4 ;
      RECT 0.00000 5.04000 0.02400 5.06400 ;
    END
  END rb_data[52]
  PIN rb_data[53]
    DIRECTION OUTPUT ;
    USE SIGNAL ;
    PORT
      LAYER M4 ;
      RECT 0.00000 5.13600 0.02400 5.16000 ;
    END
  END rb_data[53]
  PIN rb_data[54]
    DIRECTION OUTPUT ;
    USE SIGNAL ;
    PORT
      LAYER M4 ;
      RECT 0.00000 5.23200 0.02400 5.25600 ;
    END
  END rb_data[54]
  PIN rb_data[55]
    DIRECTION OUTPUT ;
    USE SIGNAL ;
    PORT
      LAYER M4 ;
      RECT 0.00000 5.32800 0.02400 5.35200 ;
    END
  END rb_data[55]
  PIN rb_data[56]
    DIRECTION OUTPUT ;
    USE SIGNAL ;
    PORT
      LAYER M4 ;
      RECT 0.00000 5.42400 0.02400 5.44800 ;
    END
  END rb_data[56]
  PIN rb_data[57]
    DIRECTION OUTPUT ;
    USE SIGNAL ;
    PORT
      LAYER M4 ;
      RECT 0.00000 5.52000 0.02400 5.54400 ;
    END
  END rb_data[57]
  PIN rb_data[58]
    DIRECTION OUTPUT ;
    USE SIGNAL ;
    PORT
      LAYER M4 ;
      RECT 0.00000 5.61600 0.02400 5.64000 ;
    END
  END rb_data[58]
  PIN rb_data[59]
    DIRECTION OUTPUT ;
    USE SIGNAL ;
    PORT
      LAYER M4 ;
      RECT 0.00000 5.71200 0.02400 5.73600 ;
    END
  END rb_data[59]
  PIN rb_data[60]
    DIRECTION OUTPUT ;
    USE SIGNAL ;
    PORT
      LAYER M4 ;
      RECT 0.00000 5.80800 0.02400 5.83200 ;
    END
  END rb_data[60]
  PIN rb_data[61]
    DIRECTION OUTPUT ;
    USE SIGNAL ;
    PORT
      LAYER M4 ;
      RECT 0.00000 5.90400 0.02400 5.92800 ;
    END
  END rb_data[61]
  PIN rb_data[62]
    DIRECTION OUTPUT ;
    USE SIGNAL ;
    PORT
      LAYER M4 ;
      RECT 0.00000 6.00000 0.02400 6.02400 ;
    END
  END rb_data[62]
  PIN rb_data[63]
    DIRECTION OUTPUT ;
    USE SIGNAL ;
    PORT
      LAYER M4 ;
      RECT 0.00000 6.09600 0.02400 6.12000 ;
    END
  END rb_data[63]
  PIN rb_data[64]
    DIRECTION OUTPUT ;
    USE SIGNAL ;
    PORT
      LAYER M4 ;
      RECT 0.00000 6.19200 0.02400 6.21600 ;
    END
  END rb_data[64]
  PIN rb_data[65]
    DIRECTION OUTPUT ;
    USE SIGNAL ;
    PORT
      LAYER M4 ;
      RECT 0.00000 6.28800 0.02400 6.31200 ;
    END
  END rb_data[65]
  PIN rb_data[66]
    DIRECTION OUTPUT ;
    USE SIGNAL ;
    PORT
      LAYER M4 ;
      RECT 0.00000 6.38400 0.02400 6.40800 ;
    END
  END rb_data[66]
  PIN rb_data[67]
    DIRECTION OUTPUT ;
    USE SIGNAL ;
    PORT
      LAYER M4 ;
      RECT 0.00000 6.48000 0.02400 6.50400 ;
    END
  END rb_data[67]
  PIN rb_data[68]
    DIRECTION OUTPUT ;
    USE SIGNAL ;
    PORT
      LAYER M4 ;
      RECT 0.00000 6.57600 0.02400 6.60000 ;
    END
  END rb_data[68]
  PIN rb_data[69]
    DIRECTION OUTPUT ;
    USE SIGNAL ;
    PORT
      LAYER M4 ;
      RECT 0.00000 6.67200 0.02400 6.69600 ;
    END
  END rb_data[69]
  PIN rb_data[70]
    DIRECTION OUTPUT ;
    USE SIGNAL ;
    PORT
      LAYER M4 ;
      RECT 0.00000 6.76800 0.02400 6.79200 ;
    END
  END rb_data[70]
  PIN rb_data[71]
    DIRECTION OUTPUT ;
    USE SIGNAL ;
    PORT
      LAYER M4 ;
      RECT 0.00000 6.86400 0.02400 6.88800 ;
    END
  END rb_data[71]
  PIN rb_data[72]
    DIRECTION OUTPUT ;
    USE SIGNAL ;
    PORT
      LAYER M4 ;
      RECT 0.00000 6.96000 0.02400 6.98400 ;
    END
  END rb_data[72]
  PIN rb_data[73]
    DIRECTION OUTPUT ;
    USE SIGNAL ;
    PORT
      LAYER M4 ;
      RECT 0.00000 7.05600 0.02400 7.08000 ;
    END
  END rb_data[73]
  PIN rb_data[74]
    DIRECTION OUTPUT ;
    USE SIGNAL ;
    PORT
      LAYER M4 ;
      RECT 0.00000 7.15200 0.02400 7.17600 ;
    END
  END rb_data[74]
  PIN rb_data[75]
    DIRECTION OUTPUT ;
    USE SIGNAL ;
    PORT
      LAYER M4 ;
      RECT 0.00000 7.24800 0.02400 7.27200 ;
    END
  END rb_data[75]
  PIN rb_data[76]
    DIRECTION OUTPUT ;
    USE SIGNAL ;
    PORT
      LAYER M4 ;
      RECT 0.00000 7.34400 0.02400 7.36800 ;
    END
  END rb_data[76]
  PIN rb_data[77]
    DIRECTION OUTPUT ;
    USE SIGNAL ;
    PORT
      LAYER M4 ;
      RECT 0.00000 7.44000 0.02400 7.46400 ;
    END
  END rb_data[77]
  PIN rb_data[78]
    DIRECTION OUTPUT ;
    USE SIGNAL ;
    PORT
      LAYER M4 ;
      RECT 0.00000 7.53600 0.02400 7.56000 ;
    END
  END rb_data[78]
  PIN rb_data[79]
    DIRECTION OUTPUT ;
    USE SIGNAL ;
    PORT
      LAYER M4 ;
      RECT 0.00000 7.63200 0.02400 7.65600 ;
    END
  END rb_data[79]
  PIN rb_data[80]
    DIRECTION OUTPUT ;
    USE SIGNAL ;
    PORT
      LAYER M4 ;
      RECT 0.00000 7.72800 0.02400 7.75200 ;
    END
  END rb_data[80]
  PIN rb_data[81]
    DIRECTION OUTPUT ;
    USE SIGNAL ;
    PORT
      LAYER M4 ;
      RECT 0.00000 7.82400 0.02400 7.84800 ;
    END
  END rb_data[81]
  PIN rb_data[82]
    DIRECTION OUTPUT ;
    USE SIGNAL ;
    PORT
      LAYER M4 ;
      RECT 0.00000 7.92000 0.02400 7.94400 ;
    END
  END rb_data[82]
  PIN rb_data[83]
    DIRECTION OUTPUT ;
    USE SIGNAL ;
    PORT
      LAYER M4 ;
      RECT 0.00000 8.01600 0.02400 8.04000 ;
    END
  END rb_data[83]
  PIN rb_data[84]
    DIRECTION OUTPUT ;
    USE SIGNAL ;
    PORT
      LAYER M4 ;
      RECT 0.00000 8.11200 0.02400 8.13600 ;
    END
  END rb_data[84]
  PIN rb_data[85]
    DIRECTION OUTPUT ;
    USE SIGNAL ;
    PORT
      LAYER M4 ;
      RECT 0.00000 8.20800 0.02400 8.23200 ;
    END
  END rb_data[85]
  PIN rb_data[86]
    DIRECTION OUTPUT ;
    USE SIGNAL ;
    PORT
      LAYER M4 ;
      RECT 0.00000 8.30400 0.02400 8.32800 ;
    END
  END rb_data[86]
  PIN rb_data[87]
    DIRECTION OUTPUT ;
    USE SIGNAL ;
    PORT
      LAYER M4 ;
      RECT 0.00000 8.40000 0.02400 8.42400 ;
    END
  END rb_data[87]
  PIN rb_data[88]
    DIRECTION OUTPUT ;
    USE SIGNAL ;
    PORT
      LAYER M4 ;
      RECT 0.00000 8.49600 0.02400 8.52000 ;
    END
  END rb_data[88]
  PIN rb_data[89]
    DIRECTION OUTPUT ;
    USE SIGNAL ;
    PORT
      LAYER M4 ;
      RECT 0.00000 8.59200 0.02400 8.61600 ;
    END
  END rb_data[89]
  PIN rb_data[90]
    DIRECTION OUTPUT ;
    USE SIGNAL ;
    PORT
      LAYER M4 ;
      RECT 0.00000 8.68800 0.02400 8.71200 ;
    END
  END rb_data[90]
  PIN rb_data[91]
    DIRECTION OUTPUT ;
    USE SIGNAL ;
    PORT
      LAYER M4 ;
      RECT 0.00000 8.78400 0.02400 8.80800 ;
    END
  END rb_data[91]
  PIN rb_data[92]
    DIRECTION OUTPUT ;
    USE SIGNAL ;
    PORT
      LAYER M4 ;
      RECT 0.00000 8.88000 0.02400 8.90400 ;
    END
  END rb_data[92]
  PIN rb_data[93]
    DIRECTION OUTPUT ;
    USE SIGNAL ;
    PORT
      LAYER M4 ;
      RECT 0.00000 8.97600 0.02400 9.00000 ;
    END
  END rb_data[93]
  PIN rb_data[94]
    DIRECTION OUTPUT ;
    USE SIGNAL ;
    PORT
      LAYER M4 ;
      RECT 0.00000 9.07200 0.02400 9.09600 ;
    END
  END rb_data[94]
  PIN rb_data[95]
    DIRECTION OUTPUT ;
    USE SIGNAL ;
    PORT
      LAYER M4 ;
      RECT 0.00000 9.16800 0.02400 9.19200 ;
    END
  END rb_data[95]
  PIN rb_data[96]
    DIRECTION OUTPUT ;
    USE SIGNAL ;
    PORT
      LAYER M4 ;
      RECT 0.00000 9.26400 0.02400 9.28800 ;
    END
  END rb_data[96]
  PIN rb_data[97]
    DIRECTION OUTPUT ;
    USE SIGNAL ;
    PORT
      LAYER M4 ;
      RECT 0.00000 9.36000 0.02400 9.38400 ;
    END
  END rb_data[97]
  PIN rb_data[98]
    DIRECTION OUTPUT ;
    USE SIGNAL ;
    PORT
      LAYER M4 ;
      RECT 0.00000 9.45600 0.02400 9.48000 ;
    END
  END rb_data[98]
  PIN rb_data[99]
    DIRECTION OUTPUT ;
    USE SIGNAL ;
    PORT
      LAYER M4 ;
      RECT 0.00000 9.55200 0.02400 9.57600 ;
    END
  END rb_data[99]
  PIN rb_data[100]
    DIRECTION OUTPUT ;
    USE SIGNAL ;
    PORT
      LAYER M4 ;
      RECT 0.00000 9.64800 0.02400 9.67200 ;
    END
  END rb_data[100]
  PIN rb_data[101]
    DIRECTION OUTPUT ;
    USE SIGNAL ;
    PORT
      LAYER M4 ;
      RECT 0.00000 9.74400 0.02400 9.76800 ;
    END
  END rb_data[101]
  PIN rb_data[102]
    DIRECTION OUTPUT ;
    USE SIGNAL ;
    PORT
      LAYER M4 ;
      RECT 0.00000 9.84000 0.02400 9.86400 ;
    END
  END rb_data[102]
  PIN rb_data[103]
    DIRECTION OUTPUT ;
    USE SIGNAL ;
    PORT
      LAYER M4 ;
      RECT 0.00000 9.93600 0.02400 9.96000 ;
    END
  END rb_data[103]
  PIN rb_data[104]
    DIRECTION OUTPUT ;
    USE SIGNAL ;
    PORT
      LAYER M4 ;
      RECT 0.00000 10.03200 0.02400 10.05600 ;
    END
  END rb_data[104]
  PIN rb_data[105]
    DIRECTION OUTPUT ;
    USE SIGNAL ;
    PORT
      LAYER M4 ;
      RECT 0.00000 10.12800 0.02400 10.15200 ;
    END
  END rb_data[105]
  PIN rb_data[106]
    DIRECTION OUTPUT ;
    USE SIGNAL ;
    PORT
      LAYER M4 ;
      RECT 0.00000 10.22400 0.02400 10.24800 ;
    END
  END rb_data[106]
  PIN rb_data[107]
    DIRECTION OUTPUT ;
    USE SIGNAL ;
    PORT
      LAYER M4 ;
      RECT 0.00000 10.32000 0.02400 10.34400 ;
    END
  END rb_data[107]
  PIN rb_data[108]
    DIRECTION OUTPUT ;
    USE SIGNAL ;
    PORT
      LAYER M4 ;
      RECT 0.00000 10.41600 0.02400 10.44000 ;
    END
  END rb_data[108]
  PIN rb_data[109]
    DIRECTION OUTPUT ;
    USE SIGNAL ;
    PORT
      LAYER M4 ;
      RECT 0.00000 10.51200 0.02400 10.53600 ;
    END
  END rb_data[109]
  PIN rb_data[110]
    DIRECTION OUTPUT ;
    USE SIGNAL ;
    PORT
      LAYER M4 ;
      RECT 0.00000 10.60800 0.02400 10.63200 ;
    END
  END rb_data[110]
  PIN rb_data[111]
    DIRECTION OUTPUT ;
    USE SIGNAL ;
    PORT
      LAYER M4 ;
      RECT 0.00000 10.70400 0.02400 10.72800 ;
    END
  END rb_data[111]
  PIN rb_data[112]
    DIRECTION OUTPUT ;
    USE SIGNAL ;
    PORT
      LAYER M4 ;
      RECT 0.00000 10.80000 0.02400 10.82400 ;
    END
  END rb_data[112]
  PIN rb_data[113]
    DIRECTION OUTPUT ;
    USE SIGNAL ;
    PORT
      LAYER M4 ;
      RECT 0.00000 10.89600 0.02400 10.92000 ;
    END
  END rb_data[113]
  PIN rb_data[114]
    DIRECTION OUTPUT ;
    USE SIGNAL ;
    PORT
      LAYER M4 ;
      RECT 0.00000 10.99200 0.02400 11.01600 ;
    END
  END rb_data[114]
  PIN rb_data[115]
    DIRECTION OUTPUT ;
    USE SIGNAL ;
    PORT
      LAYER M4 ;
      RECT 0.00000 11.08800 0.02400 11.11200 ;
    END
  END rb_data[115]
  PIN rb_data[116]
    DIRECTION OUTPUT ;
    USE SIGNAL ;
    PORT
      LAYER M4 ;
      RECT 0.00000 11.18400 0.02400 11.20800 ;
    END
  END rb_data[116]
  PIN rb_data[117]
    DIRECTION OUTPUT ;
    USE SIGNAL ;
    PORT
      LAYER M4 ;
      RECT 0.00000 11.28000 0.02400 11.30400 ;
    END
  END rb_data[117]
  PIN rb_data[118]
    DIRECTION OUTPUT ;
    USE SIGNAL ;
    PORT
      LAYER M4 ;
      RECT 0.00000 11.37600 0.02400 11.40000 ;
    END
  END rb_data[118]
  PIN rb_data[119]
    DIRECTION OUTPUT ;
    USE SIGNAL ;
    PORT
      LAYER M4 ;
      RECT 0.00000 11.47200 0.02400 11.49600 ;
    END
  END rb_data[119]
  PIN rb_data[120]
    DIRECTION OUTPUT ;
    USE SIGNAL ;
    PORT
      LAYER M4 ;
      RECT 0.00000 11.56800 0.02400 11.59200 ;
    END
  END rb_data[120]
  PIN rb_data[121]
    DIRECTION OUTPUT ;
    USE SIGNAL ;
    PORT
      LAYER M4 ;
      RECT 0.00000 11.66400 0.02400 11.68800 ;
    END
  END rb_data[121]
  PIN rb_data[122]
    DIRECTION OUTPUT ;
    USE SIGNAL ;
    PORT
      LAYER M4 ;
      RECT 0.00000 11.76000 0.02400 11.78400 ;
    END
  END rb_data[122]
  PIN rb_data[123]
    DIRECTION OUTPUT ;
    USE SIGNAL ;
    PORT
      LAYER M4 ;
      RECT 0.00000 11.85600 0.02400 11.88000 ;
    END
  END rb_data[123]
  PIN rb_data[124]
    DIRECTION OUTPUT ;
    USE SIGNAL ;
    PORT
      LAYER M4 ;
      RECT 0.00000 11.95200 0.02400 11.97600 ;
    END
  END rb_data[124]
  PIN rb_data[125]
    DIRECTION OUTPUT ;
    USE SIGNAL ;
    PORT
      LAYER M4 ;
      RECT 0.00000 12.04800 0.02400 12.07200 ;
    END
  END rb_data[125]
  PIN rb_data[126]
    DIRECTION OUTPUT ;
    USE SIGNAL ;
    PORT
      LAYER M4 ;
      RECT 0.00000 12.14400 0.02400 12.16800 ;
    END
  END rb_data[126]
  PIN rb_data[127]
    DIRECTION OUTPUT ;
    USE SIGNAL ;
    PORT
      LAYER M4 ;
      RECT 0.00000 12.24000 0.02400 12.26400 ;
    END
  END rb_data[127]
  PIN rb_data[128]
    DIRECTION OUTPUT ;
    USE SIGNAL ;
    PORT
      LAYER M4 ;
      RECT 0.00000 12.33600 0.02400 12.36000 ;
    END
  END rb_data[128]
  PIN rb_data[129]
    DIRECTION OUTPUT ;
    USE SIGNAL ;
    PORT
      LAYER M4 ;
      RECT 0.00000 12.43200 0.02400 12.45600 ;
    END
  END rb_data[129]
  PIN rb_data[130]
    DIRECTION OUTPUT ;
    USE SIGNAL ;
    PORT
      LAYER M4 ;
      RECT 0.00000 12.52800 0.02400 12.55200 ;
    END
  END rb_data[130]
  PIN rb_data[131]
    DIRECTION OUTPUT ;
    USE SIGNAL ;
    PORT
      LAYER M4 ;
      RECT 0.00000 12.62400 0.02400 12.64800 ;
    END
  END rb_data[131]
  PIN rb_data[132]
    DIRECTION OUTPUT ;
    USE SIGNAL ;
    PORT
      LAYER M4 ;
      RECT 0.00000 12.72000 0.02400 12.74400 ;
    END
  END rb_data[132]
  PIN rb_data[133]
    DIRECTION OUTPUT ;
    USE SIGNAL ;
    PORT
      LAYER M4 ;
      RECT 0.00000 12.81600 0.02400 12.84000 ;
    END
  END rb_data[133]
  PIN rb_data[134]
    DIRECTION OUTPUT ;
    USE SIGNAL ;
    PORT
      LAYER M4 ;
      RECT 0.00000 12.91200 0.02400 12.93600 ;
    END
  END rb_data[134]
  PIN rb_data[135]
    DIRECTION OUTPUT ;
    USE SIGNAL ;
    PORT
      LAYER M4 ;
      RECT 0.00000 13.00800 0.02400 13.03200 ;
    END
  END rb_data[135]
  PIN rb_data[136]
    DIRECTION OUTPUT ;
    USE SIGNAL ;
    PORT
      LAYER M4 ;
      RECT 0.00000 13.10400 0.02400 13.12800 ;
    END
  END rb_data[136]
  PIN rb_data[137]
    DIRECTION OUTPUT ;
    USE SIGNAL ;
    PORT
      LAYER M4 ;
      RECT 0.00000 13.20000 0.02400 13.22400 ;
    END
  END rb_data[137]
  PIN rb_data[138]
    DIRECTION OUTPUT ;
    USE SIGNAL ;
    PORT
      LAYER M4 ;
      RECT 0.00000 13.29600 0.02400 13.32000 ;
    END
  END rb_data[138]
  PIN rb_data[139]
    DIRECTION OUTPUT ;
    USE SIGNAL ;
    PORT
      LAYER M4 ;
      RECT 0.00000 13.39200 0.02400 13.41600 ;
    END
  END rb_data[139]
  PIN rb_data[140]
    DIRECTION OUTPUT ;
    USE SIGNAL ;
    PORT
      LAYER M4 ;
      RECT 0.00000 13.48800 0.02400 13.51200 ;
    END
  END rb_data[140]
  PIN rb_data[141]
    DIRECTION OUTPUT ;
    USE SIGNAL ;
    PORT
      LAYER M4 ;
      RECT 0.00000 13.58400 0.02400 13.60800 ;
    END
  END rb_data[141]
  PIN rb_data[142]
    DIRECTION OUTPUT ;
    USE SIGNAL ;
    PORT
      LAYER M4 ;
      RECT 0.00000 13.68000 0.02400 13.70400 ;
    END
  END rb_data[142]
  PIN rb_data[143]
    DIRECTION OUTPUT ;
    USE SIGNAL ;
    PORT
      LAYER M4 ;
      RECT 0.00000 13.77600 0.02400 13.80000 ;
    END
  END rb_data[143]
  PIN rb_data[144]
    DIRECTION OUTPUT ;
    USE SIGNAL ;
    PORT
      LAYER M4 ;
      RECT 0.00000 13.87200 0.02400 13.89600 ;
    END
  END rb_data[144]
  PIN rb_data[145]
    DIRECTION OUTPUT ;
    USE SIGNAL ;
    PORT
      LAYER M4 ;
      RECT 0.00000 13.96800 0.02400 13.99200 ;
    END
  END rb_data[145]
  PIN rb_data[146]
    DIRECTION OUTPUT ;
    USE SIGNAL ;
    PORT
      LAYER M4 ;
      RECT 0.00000 14.06400 0.02400 14.08800 ;
    END
  END rb_data[146]
  PIN rb_data[147]
    DIRECTION OUTPUT ;
    USE SIGNAL ;
    PORT
      LAYER M4 ;
      RECT 0.00000 14.16000 0.02400 14.18400 ;
    END
  END rb_data[147]
  PIN rb_data[148]
    DIRECTION OUTPUT ;
    USE SIGNAL ;
    PORT
      LAYER M4 ;
      RECT 0.00000 14.25600 0.02400 14.28000 ;
    END
  END rb_data[148]
  PIN rb_data[149]
    DIRECTION OUTPUT ;
    USE SIGNAL ;
    PORT
      LAYER M4 ;
      RECT 0.00000 14.35200 0.02400 14.37600 ;
    END
  END rb_data[149]
  PIN rb_data[150]
    DIRECTION OUTPUT ;
    USE SIGNAL ;
    PORT
      LAYER M4 ;
      RECT 0.00000 14.44800 0.02400 14.47200 ;
    END
  END rb_data[150]
  PIN rb_data[151]
    DIRECTION OUTPUT ;
    USE SIGNAL ;
    PORT
      LAYER M4 ;
      RECT 0.00000 14.54400 0.02400 14.56800 ;
    END
  END rb_data[151]
  PIN rb_data[152]
    DIRECTION OUTPUT ;
    USE SIGNAL ;
    PORT
      LAYER M4 ;
      RECT 0.00000 14.64000 0.02400 14.66400 ;
    END
  END rb_data[152]
  PIN rb_data[153]
    DIRECTION OUTPUT ;
    USE SIGNAL ;
    PORT
      LAYER M4 ;
      RECT 0.00000 14.73600 0.02400 14.76000 ;
    END
  END rb_data[153]
  PIN rb_data[154]
    DIRECTION OUTPUT ;
    USE SIGNAL ;
    PORT
      LAYER M4 ;
      RECT 0.00000 14.83200 0.02400 14.85600 ;
    END
  END rb_data[154]
  PIN rb_data[155]
    DIRECTION OUTPUT ;
    USE SIGNAL ;
    PORT
      LAYER M4 ;
      RECT 0.00000 14.92800 0.02400 14.95200 ;
    END
  END rb_data[155]
  PIN rb_data[156]
    DIRECTION OUTPUT ;
    USE SIGNAL ;
    PORT
      LAYER M4 ;
      RECT 0.00000 15.02400 0.02400 15.04800 ;
    END
  END rb_data[156]
  PIN rb_data[157]
    DIRECTION OUTPUT ;
    USE SIGNAL ;
    PORT
      LAYER M4 ;
      RECT 0.00000 15.12000 0.02400 15.14400 ;
    END
  END rb_data[157]
  PIN rb_data[158]
    DIRECTION OUTPUT ;
    USE SIGNAL ;
    PORT
      LAYER M4 ;
      RECT 0.00000 15.21600 0.02400 15.24000 ;
    END
  END rb_data[158]
  PIN rb_data[159]
    DIRECTION OUTPUT ;
    USE SIGNAL ;
    PORT
      LAYER M4 ;
      RECT 0.00000 15.31200 0.02400 15.33600 ;
    END
  END rb_data[159]
  PIN rb_data[160]
    DIRECTION OUTPUT ;
    USE SIGNAL ;
    PORT
      LAYER M4 ;
      RECT 0.00000 15.40800 0.02400 15.43200 ;
    END
  END rb_data[160]
  PIN rb_data[161]
    DIRECTION OUTPUT ;
    USE SIGNAL ;
    PORT
      LAYER M4 ;
      RECT 0.00000 15.50400 0.02400 15.52800 ;
    END
  END rb_data[161]
  PIN rb_data[162]
    DIRECTION OUTPUT ;
    USE SIGNAL ;
    PORT
      LAYER M4 ;
      RECT 0.00000 15.60000 0.02400 15.62400 ;
    END
  END rb_data[162]
  PIN rb_data[163]
    DIRECTION OUTPUT ;
    USE SIGNAL ;
    PORT
      LAYER M4 ;
      RECT 0.00000 15.69600 0.02400 15.72000 ;
    END
  END rb_data[163]
  PIN rb_data[164]
    DIRECTION OUTPUT ;
    USE SIGNAL ;
    PORT
      LAYER M4 ;
      RECT 0.00000 15.79200 0.02400 15.81600 ;
    END
  END rb_data[164]
  PIN rb_data[165]
    DIRECTION OUTPUT ;
    USE SIGNAL ;
    PORT
      LAYER M4 ;
      RECT 0.00000 15.88800 0.02400 15.91200 ;
    END
  END rb_data[165]
  PIN rb_data[166]
    DIRECTION OUTPUT ;
    USE SIGNAL ;
    PORT
      LAYER M4 ;
      RECT 0.00000 15.98400 0.02400 16.00800 ;
    END
  END rb_data[166]
  PIN rb_data[167]
    DIRECTION OUTPUT ;
    USE SIGNAL ;
    PORT
      LAYER M4 ;
      RECT 0.00000 16.08000 0.02400 16.10400 ;
    END
  END rb_data[167]
  PIN rb_data[168]
    DIRECTION OUTPUT ;
    USE SIGNAL ;
    PORT
      LAYER M4 ;
      RECT 0.00000 16.17600 0.02400 16.20000 ;
    END
  END rb_data[168]
  PIN rb_data[169]
    DIRECTION OUTPUT ;
    USE SIGNAL ;
    PORT
      LAYER M4 ;
      RECT 0.00000 16.27200 0.02400 16.29600 ;
    END
  END rb_data[169]
  PIN rb_data[170]
    DIRECTION OUTPUT ;
    USE SIGNAL ;
    PORT
      LAYER M4 ;
      RECT 0.00000 16.36800 0.02400 16.39200 ;
    END
  END rb_data[170]
  PIN rb_data[171]
    DIRECTION OUTPUT ;
    USE SIGNAL ;
    PORT
      LAYER M4 ;
      RECT 0.00000 16.46400 0.02400 16.48800 ;
    END
  END rb_data[171]
  PIN rb_data[172]
    DIRECTION OUTPUT ;
    USE SIGNAL ;
    PORT
      LAYER M4 ;
      RECT 0.00000 16.56000 0.02400 16.58400 ;
    END
  END rb_data[172]
  PIN rb_data[173]
    DIRECTION OUTPUT ;
    USE SIGNAL ;
    PORT
      LAYER M4 ;
      RECT 0.00000 16.65600 0.02400 16.68000 ;
    END
  END rb_data[173]
  PIN rb_data[174]
    DIRECTION OUTPUT ;
    USE SIGNAL ;
    PORT
      LAYER M4 ;
      RECT 0.00000 16.75200 0.02400 16.77600 ;
    END
  END rb_data[174]
  PIN rb_data[175]
    DIRECTION OUTPUT ;
    USE SIGNAL ;
    PORT
      LAYER M4 ;
      RECT 0.00000 16.84800 0.02400 16.87200 ;
    END
  END rb_data[175]
  PIN rb_data[176]
    DIRECTION OUTPUT ;
    USE SIGNAL ;
    PORT
      LAYER M4 ;
      RECT 0.00000 16.94400 0.02400 16.96800 ;
    END
  END rb_data[176]
  PIN rb_data[177]
    DIRECTION OUTPUT ;
    USE SIGNAL ;
    PORT
      LAYER M4 ;
      RECT 0.00000 17.04000 0.02400 17.06400 ;
    END
  END rb_data[177]
  PIN rb_data[178]
    DIRECTION OUTPUT ;
    USE SIGNAL ;
    PORT
      LAYER M4 ;
      RECT 0.00000 17.13600 0.02400 17.16000 ;
    END
  END rb_data[178]
  PIN rb_data[179]
    DIRECTION OUTPUT ;
    USE SIGNAL ;
    PORT
      LAYER M4 ;
      RECT 0.00000 17.23200 0.02400 17.25600 ;
    END
  END rb_data[179]
  PIN rb_data[180]
    DIRECTION OUTPUT ;
    USE SIGNAL ;
    PORT
      LAYER M4 ;
      RECT 0.00000 17.32800 0.02400 17.35200 ;
    END
  END rb_data[180]
  PIN rb_data[181]
    DIRECTION OUTPUT ;
    USE SIGNAL ;
    PORT
      LAYER M4 ;
      RECT 0.00000 17.42400 0.02400 17.44800 ;
    END
  END rb_data[181]
  PIN rb_data[182]
    DIRECTION OUTPUT ;
    USE SIGNAL ;
    PORT
      LAYER M4 ;
      RECT 0.00000 17.52000 0.02400 17.54400 ;
    END
  END rb_data[182]
  PIN rb_data[183]
    DIRECTION OUTPUT ;
    USE SIGNAL ;
    PORT
      LAYER M4 ;
      RECT 0.00000 17.61600 0.02400 17.64000 ;
    END
  END rb_data[183]
  PIN rb_data[184]
    DIRECTION OUTPUT ;
    USE SIGNAL ;
    PORT
      LAYER M4 ;
      RECT 0.00000 17.71200 0.02400 17.73600 ;
    END
  END rb_data[184]
  PIN rb_data[185]
    DIRECTION OUTPUT ;
    USE SIGNAL ;
    PORT
      LAYER M4 ;
      RECT 0.00000 17.80800 0.02400 17.83200 ;
    END
  END rb_data[185]
  PIN rb_data[186]
    DIRECTION OUTPUT ;
    USE SIGNAL ;
    PORT
      LAYER M4 ;
      RECT 0.00000 17.90400 0.02400 17.92800 ;
    END
  END rb_data[186]
  PIN rb_data[187]
    DIRECTION OUTPUT ;
    USE SIGNAL ;
    PORT
      LAYER M4 ;
      RECT 0.00000 18.00000 0.02400 18.02400 ;
    END
  END rb_data[187]
  PIN rb_data[188]
    DIRECTION OUTPUT ;
    USE SIGNAL ;
    PORT
      LAYER M4 ;
      RECT 0.00000 18.09600 0.02400 18.12000 ;
    END
  END rb_data[188]
  PIN rb_data[189]
    DIRECTION OUTPUT ;
    USE SIGNAL ;
    PORT
      LAYER M4 ;
      RECT 0.00000 18.19200 0.02400 18.21600 ;
    END
  END rb_data[189]
  PIN rb_data[190]
    DIRECTION OUTPUT ;
    USE SIGNAL ;
    PORT
      LAYER M4 ;
      RECT 0.00000 18.28800 0.02400 18.31200 ;
    END
  END rb_data[190]
  PIN rb_data[191]
    DIRECTION OUTPUT ;
    USE SIGNAL ;
    PORT
      LAYER M4 ;
      RECT 0.00000 18.38400 0.02400 18.40800 ;
    END
  END rb_data[191]
  PIN rb_data[192]
    DIRECTION OUTPUT ;
    USE SIGNAL ;
    PORT
      LAYER M4 ;
      RECT 0.00000 18.48000 0.02400 18.50400 ;
    END
  END rb_data[192]
  PIN rb_data[193]
    DIRECTION OUTPUT ;
    USE SIGNAL ;
    PORT
      LAYER M4 ;
      RECT 0.00000 18.57600 0.02400 18.60000 ;
    END
  END rb_data[193]
  PIN rb_data[194]
    DIRECTION OUTPUT ;
    USE SIGNAL ;
    PORT
      LAYER M4 ;
      RECT 0.00000 18.67200 0.02400 18.69600 ;
    END
  END rb_data[194]
  PIN rb_data[195]
    DIRECTION OUTPUT ;
    USE SIGNAL ;
    PORT
      LAYER M4 ;
      RECT 0.00000 18.76800 0.02400 18.79200 ;
    END
  END rb_data[195]
  PIN rb_data[196]
    DIRECTION OUTPUT ;
    USE SIGNAL ;
    PORT
      LAYER M4 ;
      RECT 0.00000 18.86400 0.02400 18.88800 ;
    END
  END rb_data[196]
  PIN rb_data[197]
    DIRECTION OUTPUT ;
    USE SIGNAL ;
    PORT
      LAYER M4 ;
      RECT 0.00000 18.96000 0.02400 18.98400 ;
    END
  END rb_data[197]
  PIN rb_data[198]
    DIRECTION OUTPUT ;
    USE SIGNAL ;
    PORT
      LAYER M4 ;
      RECT 0.00000 19.05600 0.02400 19.08000 ;
    END
  END rb_data[198]
  PIN rb_data[199]
    DIRECTION OUTPUT ;
    USE SIGNAL ;
    PORT
      LAYER M4 ;
      RECT 0.00000 19.15200 0.02400 19.17600 ;
    END
  END rb_data[199]
  PIN rb_data[200]
    DIRECTION OUTPUT ;
    USE SIGNAL ;
    PORT
      LAYER M4 ;
      RECT 0.00000 19.24800 0.02400 19.27200 ;
    END
  END rb_data[200]
  PIN rb_data[201]
    DIRECTION OUTPUT ;
    USE SIGNAL ;
    PORT
      LAYER M4 ;
      RECT 0.00000 19.34400 0.02400 19.36800 ;
    END
  END rb_data[201]
  PIN rb_data[202]
    DIRECTION OUTPUT ;
    USE SIGNAL ;
    PORT
      LAYER M4 ;
      RECT 0.00000 19.44000 0.02400 19.46400 ;
    END
  END rb_data[202]
  PIN rb_data[203]
    DIRECTION OUTPUT ;
    USE SIGNAL ;
    PORT
      LAYER M4 ;
      RECT 0.00000 19.53600 0.02400 19.56000 ;
    END
  END rb_data[203]
  PIN rb_data[204]
    DIRECTION OUTPUT ;
    USE SIGNAL ;
    PORT
      LAYER M4 ;
      RECT 0.00000 19.63200 0.02400 19.65600 ;
    END
  END rb_data[204]
  PIN rb_data[205]
    DIRECTION OUTPUT ;
    USE SIGNAL ;
    PORT
      LAYER M4 ;
      RECT 0.00000 19.72800 0.02400 19.75200 ;
    END
  END rb_data[205]
  PIN rb_data[206]
    DIRECTION OUTPUT ;
    USE SIGNAL ;
    PORT
      LAYER M4 ;
      RECT 0.00000 19.82400 0.02400 19.84800 ;
    END
  END rb_data[206]
  PIN rb_data[207]
    DIRECTION OUTPUT ;
    USE SIGNAL ;
    PORT
      LAYER M4 ;
      RECT 0.00000 19.92000 0.02400 19.94400 ;
    END
  END rb_data[207]
  PIN rb_data[208]
    DIRECTION OUTPUT ;
    USE SIGNAL ;
    PORT
      LAYER M4 ;
      RECT 0.00000 20.01600 0.02400 20.04000 ;
    END
  END rb_data[208]
  PIN rb_data[209]
    DIRECTION OUTPUT ;
    USE SIGNAL ;
    PORT
      LAYER M4 ;
      RECT 0.00000 20.11200 0.02400 20.13600 ;
    END
  END rb_data[209]
  PIN rb_data[210]
    DIRECTION OUTPUT ;
    USE SIGNAL ;
    PORT
      LAYER M4 ;
      RECT 0.00000 20.20800 0.02400 20.23200 ;
    END
  END rb_data[210]
  PIN rb_data[211]
    DIRECTION OUTPUT ;
    USE SIGNAL ;
    PORT
      LAYER M4 ;
      RECT 0.00000 20.30400 0.02400 20.32800 ;
    END
  END rb_data[211]
  PIN rb_data[212]
    DIRECTION OUTPUT ;
    USE SIGNAL ;
    PORT
      LAYER M4 ;
      RECT 0.00000 20.40000 0.02400 20.42400 ;
    END
  END rb_data[212]
  PIN rb_data[213]
    DIRECTION OUTPUT ;
    USE SIGNAL ;
    PORT
      LAYER M4 ;
      RECT 0.00000 20.49600 0.02400 20.52000 ;
    END
  END rb_data[213]
  PIN rb_data[214]
    DIRECTION OUTPUT ;
    USE SIGNAL ;
    PORT
      LAYER M4 ;
      RECT 0.00000 20.59200 0.02400 20.61600 ;
    END
  END rb_data[214]
  PIN rb_data[215]
    DIRECTION OUTPUT ;
    USE SIGNAL ;
    PORT
      LAYER M4 ;
      RECT 0.00000 20.68800 0.02400 20.71200 ;
    END
  END rb_data[215]
  PIN rb_data[216]
    DIRECTION OUTPUT ;
    USE SIGNAL ;
    PORT
      LAYER M4 ;
      RECT 0.00000 20.78400 0.02400 20.80800 ;
    END
  END rb_data[216]
  PIN rb_data[217]
    DIRECTION OUTPUT ;
    USE SIGNAL ;
    PORT
      LAYER M4 ;
      RECT 0.00000 20.88000 0.02400 20.90400 ;
    END
  END rb_data[217]
  PIN rb_data[218]
    DIRECTION OUTPUT ;
    USE SIGNAL ;
    PORT
      LAYER M4 ;
      RECT 0.00000 20.97600 0.02400 21.00000 ;
    END
  END rb_data[218]
  PIN rb_data[219]
    DIRECTION OUTPUT ;
    USE SIGNAL ;
    PORT
      LAYER M4 ;
      RECT 0.00000 21.07200 0.02400 21.09600 ;
    END
  END rb_data[219]
  PIN rb_data[220]
    DIRECTION OUTPUT ;
    USE SIGNAL ;
    PORT
      LAYER M4 ;
      RECT 0.00000 21.16800 0.02400 21.19200 ;
    END
  END rb_data[220]
  PIN rb_data[221]
    DIRECTION OUTPUT ;
    USE SIGNAL ;
    PORT
      LAYER M4 ;
      RECT 0.00000 21.26400 0.02400 21.28800 ;
    END
  END rb_data[221]
  PIN rb_data[222]
    DIRECTION OUTPUT ;
    USE SIGNAL ;
    PORT
      LAYER M4 ;
      RECT 0.00000 21.36000 0.02400 21.38400 ;
    END
  END rb_data[222]
  PIN rb_data[223]
    DIRECTION OUTPUT ;
    USE SIGNAL ;
    PORT
      LAYER M4 ;
      RECT 0.00000 21.45600 0.02400 21.48000 ;
    END
  END rb_data[223]
  PIN rb_data[224]
    DIRECTION OUTPUT ;
    USE SIGNAL ;
    PORT
      LAYER M4 ;
      RECT 0.00000 21.55200 0.02400 21.57600 ;
    END
  END rb_data[224]
  PIN rb_data[225]
    DIRECTION OUTPUT ;
    USE SIGNAL ;
    PORT
      LAYER M4 ;
      RECT 0.00000 21.64800 0.02400 21.67200 ;
    END
  END rb_data[225]
  PIN rb_data[226]
    DIRECTION OUTPUT ;
    USE SIGNAL ;
    PORT
      LAYER M4 ;
      RECT 0.00000 21.74400 0.02400 21.76800 ;
    END
  END rb_data[226]
  PIN rb_data[227]
    DIRECTION OUTPUT ;
    USE SIGNAL ;
    PORT
      LAYER M4 ;
      RECT 0.00000 21.84000 0.02400 21.86400 ;
    END
  END rb_data[227]
  PIN rb_data[228]
    DIRECTION OUTPUT ;
    USE SIGNAL ;
    PORT
      LAYER M4 ;
      RECT 0.00000 21.93600 0.02400 21.96000 ;
    END
  END rb_data[228]
  PIN rb_data[229]
    DIRECTION OUTPUT ;
    USE SIGNAL ;
    PORT
      LAYER M4 ;
      RECT 0.00000 22.03200 0.02400 22.05600 ;
    END
  END rb_data[229]
  PIN rb_data[230]
    DIRECTION OUTPUT ;
    USE SIGNAL ;
    PORT
      LAYER M4 ;
      RECT 0.00000 22.12800 0.02400 22.15200 ;
    END
  END rb_data[230]
  PIN rb_data[231]
    DIRECTION OUTPUT ;
    USE SIGNAL ;
    PORT
      LAYER M4 ;
      RECT 0.00000 22.22400 0.02400 22.24800 ;
    END
  END rb_data[231]
  PIN rb_data[232]
    DIRECTION OUTPUT ;
    USE SIGNAL ;
    PORT
      LAYER M4 ;
      RECT 0.00000 22.32000 0.02400 22.34400 ;
    END
  END rb_data[232]
  PIN rb_data[233]
    DIRECTION OUTPUT ;
    USE SIGNAL ;
    PORT
      LAYER M4 ;
      RECT 0.00000 22.41600 0.02400 22.44000 ;
    END
  END rb_data[233]
  PIN rb_data[234]
    DIRECTION OUTPUT ;
    USE SIGNAL ;
    PORT
      LAYER M4 ;
      RECT 0.00000 22.51200 0.02400 22.53600 ;
    END
  END rb_data[234]
  PIN rb_data[235]
    DIRECTION OUTPUT ;
    USE SIGNAL ;
    PORT
      LAYER M4 ;
      RECT 0.00000 22.60800 0.02400 22.63200 ;
    END
  END rb_data[235]
  PIN rb_data[236]
    DIRECTION OUTPUT ;
    USE SIGNAL ;
    PORT
      LAYER M4 ;
      RECT 0.00000 22.70400 0.02400 22.72800 ;
    END
  END rb_data[236]
  PIN rb_data[237]
    DIRECTION OUTPUT ;
    USE SIGNAL ;
    PORT
      LAYER M4 ;
      RECT 0.00000 22.80000 0.02400 22.82400 ;
    END
  END rb_data[237]
  PIN rb_data[238]
    DIRECTION OUTPUT ;
    USE SIGNAL ;
    PORT
      LAYER M4 ;
      RECT 0.00000 22.89600 0.02400 22.92000 ;
    END
  END rb_data[238]
  PIN rb_data[239]
    DIRECTION OUTPUT ;
    USE SIGNAL ;
    PORT
      LAYER M4 ;
      RECT 0.00000 22.99200 0.02400 23.01600 ;
    END
  END rb_data[239]
  PIN rb_data[240]
    DIRECTION OUTPUT ;
    USE SIGNAL ;
    PORT
      LAYER M4 ;
      RECT 0.00000 23.08800 0.02400 23.11200 ;
    END
  END rb_data[240]
  PIN rb_data[241]
    DIRECTION OUTPUT ;
    USE SIGNAL ;
    PORT
      LAYER M4 ;
      RECT 0.00000 23.18400 0.02400 23.20800 ;
    END
  END rb_data[241]
  PIN rb_data[242]
    DIRECTION OUTPUT ;
    USE SIGNAL ;
    PORT
      LAYER M4 ;
      RECT 0.00000 23.28000 0.02400 23.30400 ;
    END
  END rb_data[242]
  PIN rb_data[243]
    DIRECTION OUTPUT ;
    USE SIGNAL ;
    PORT
      LAYER M4 ;
      RECT 0.00000 23.37600 0.02400 23.40000 ;
    END
  END rb_data[243]
  PIN rb_data[244]
    DIRECTION OUTPUT ;
    USE SIGNAL ;
    PORT
      LAYER M4 ;
      RECT 0.00000 23.47200 0.02400 23.49600 ;
    END
  END rb_data[244]
  PIN rb_data[245]
    DIRECTION OUTPUT ;
    USE SIGNAL ;
    PORT
      LAYER M4 ;
      RECT 0.00000 23.56800 0.02400 23.59200 ;
    END
  END rb_data[245]
  PIN rb_data[246]
    DIRECTION OUTPUT ;
    USE SIGNAL ;
    PORT
      LAYER M4 ;
      RECT 0.00000 23.66400 0.02400 23.68800 ;
    END
  END rb_data[246]
  PIN rb_data[247]
    DIRECTION OUTPUT ;
    USE SIGNAL ;
    PORT
      LAYER M4 ;
      RECT 0.00000 23.76000 0.02400 23.78400 ;
    END
  END rb_data[247]
  PIN rb_data[248]
    DIRECTION OUTPUT ;
    USE SIGNAL ;
    PORT
      LAYER M4 ;
      RECT 0.00000 23.85600 0.02400 23.88000 ;
    END
  END rb_data[248]
  PIN rb_data[249]
    DIRECTION OUTPUT ;
    USE SIGNAL ;
    PORT
      LAYER M4 ;
      RECT 0.00000 23.95200 0.02400 23.97600 ;
    END
  END rb_data[249]
  PIN rb_data[250]
    DIRECTION OUTPUT ;
    USE SIGNAL ;
    PORT
      LAYER M4 ;
      RECT 0.00000 24.04800 0.02400 24.07200 ;
    END
  END rb_data[250]
  PIN rb_data[251]
    DIRECTION OUTPUT ;
    USE SIGNAL ;
    PORT
      LAYER M4 ;
      RECT 0.00000 24.14400 0.02400 24.16800 ;
    END
  END rb_data[251]
  PIN rb_data[252]
    DIRECTION OUTPUT ;
    USE SIGNAL ;
    PORT
      LAYER M4 ;
      RECT 0.00000 24.24000 0.02400 24.26400 ;
    END
  END rb_data[252]
  PIN rb_data[253]
    DIRECTION OUTPUT ;
    USE SIGNAL ;
    PORT
      LAYER M4 ;
      RECT 0.00000 24.33600 0.02400 24.36000 ;
    END
  END rb_data[253]
  PIN rb_data[254]
    DIRECTION OUTPUT ;
    USE SIGNAL ;
    PORT
      LAYER M4 ;
      RECT 0.00000 24.43200 0.02400 24.45600 ;
    END
  END rb_data[254]
  PIN rb_data[255]
    DIRECTION OUTPUT ;
    USE SIGNAL ;
    PORT
      LAYER M4 ;
      RECT 0.00000 24.52800 0.02400 24.55200 ;
    END
  END rb_data[255]
  PIN rb_data[256]
    DIRECTION OUTPUT ;
    USE SIGNAL ;
    PORT
      LAYER M4 ;
      RECT 0.00000 24.62400 0.02400 24.64800 ;
    END
  END rb_data[256]
  PIN rb_data[257]
    DIRECTION OUTPUT ;
    USE SIGNAL ;
    PORT
      LAYER M4 ;
      RECT 0.00000 24.72000 0.02400 24.74400 ;
    END
  END rb_data[257]
  PIN rb_data[258]
    DIRECTION OUTPUT ;
    USE SIGNAL ;
    PORT
      LAYER M4 ;
      RECT 0.00000 24.81600 0.02400 24.84000 ;
    END
  END rb_data[258]
  PIN rb_data[259]
    DIRECTION OUTPUT ;
    USE SIGNAL ;
    PORT
      LAYER M4 ;
      RECT 0.00000 24.91200 0.02400 24.93600 ;
    END
  END rb_data[259]
  PIN rb_data[260]
    DIRECTION OUTPUT ;
    USE SIGNAL ;
    PORT
      LAYER M4 ;
      RECT 0.00000 25.00800 0.02400 25.03200 ;
    END
  END rb_data[260]
  PIN rb_data[261]
    DIRECTION OUTPUT ;
    USE SIGNAL ;
    PORT
      LAYER M4 ;
      RECT 0.00000 25.10400 0.02400 25.12800 ;
    END
  END rb_data[261]
  PIN rb_data[262]
    DIRECTION OUTPUT ;
    USE SIGNAL ;
    PORT
      LAYER M4 ;
      RECT 0.00000 25.20000 0.02400 25.22400 ;
    END
  END rb_data[262]
  PIN rb_data[263]
    DIRECTION OUTPUT ;
    USE SIGNAL ;
    PORT
      LAYER M4 ;
      RECT 0.00000 25.29600 0.02400 25.32000 ;
    END
  END rb_data[263]
  PIN rb_data[264]
    DIRECTION OUTPUT ;
    USE SIGNAL ;
    PORT
      LAYER M4 ;
      RECT 0.00000 25.39200 0.02400 25.41600 ;
    END
  END rb_data[264]
  PIN rb_data[265]
    DIRECTION OUTPUT ;
    USE SIGNAL ;
    PORT
      LAYER M4 ;
      RECT 0.00000 25.48800 0.02400 25.51200 ;
    END
  END rb_data[265]
  PIN rb_data[266]
    DIRECTION OUTPUT ;
    USE SIGNAL ;
    PORT
      LAYER M4 ;
      RECT 0.00000 25.58400 0.02400 25.60800 ;
    END
  END rb_data[266]
  PIN rb_data[267]
    DIRECTION OUTPUT ;
    USE SIGNAL ;
    PORT
      LAYER M4 ;
      RECT 0.00000 25.68000 0.02400 25.70400 ;
    END
  END rb_data[267]
  PIN rb_data[268]
    DIRECTION OUTPUT ;
    USE SIGNAL ;
    PORT
      LAYER M4 ;
      RECT 0.00000 25.77600 0.02400 25.80000 ;
    END
  END rb_data[268]
  PIN rb_data[269]
    DIRECTION OUTPUT ;
    USE SIGNAL ;
    PORT
      LAYER M4 ;
      RECT 0.00000 25.87200 0.02400 25.89600 ;
    END
  END rb_data[269]
  PIN rb_data[270]
    DIRECTION OUTPUT ;
    USE SIGNAL ;
    PORT
      LAYER M4 ;
      RECT 0.00000 25.96800 0.02400 25.99200 ;
    END
  END rb_data[270]
  PIN rb_data[271]
    DIRECTION OUTPUT ;
    USE SIGNAL ;
    PORT
      LAYER M4 ;
      RECT 0.00000 26.06400 0.02400 26.08800 ;
    END
  END rb_data[271]
  PIN rb_data[272]
    DIRECTION OUTPUT ;
    USE SIGNAL ;
    PORT
      LAYER M4 ;
      RECT 0.00000 26.16000 0.02400 26.18400 ;
    END
  END rb_data[272]
  PIN rb_data[273]
    DIRECTION OUTPUT ;
    USE SIGNAL ;
    PORT
      LAYER M4 ;
      RECT 0.00000 26.25600 0.02400 26.28000 ;
    END
  END rb_data[273]
  PIN rb_data[274]
    DIRECTION OUTPUT ;
    USE SIGNAL ;
    PORT
      LAYER M4 ;
      RECT 0.00000 26.35200 0.02400 26.37600 ;
    END
  END rb_data[274]
  PIN rb_data[275]
    DIRECTION OUTPUT ;
    USE SIGNAL ;
    PORT
      LAYER M4 ;
      RECT 0.00000 26.44800 0.02400 26.47200 ;
    END
  END rb_data[275]
  PIN rb_data[276]
    DIRECTION OUTPUT ;
    USE SIGNAL ;
    PORT
      LAYER M4 ;
      RECT 0.00000 26.54400 0.02400 26.56800 ;
    END
  END rb_data[276]
  PIN rb_data[277]
    DIRECTION OUTPUT ;
    USE SIGNAL ;
    PORT
      LAYER M4 ;
      RECT 0.00000 26.64000 0.02400 26.66400 ;
    END
  END rb_data[277]
  PIN rb_data[278]
    DIRECTION OUTPUT ;
    USE SIGNAL ;
    PORT
      LAYER M4 ;
      RECT 0.00000 26.73600 0.02400 26.76000 ;
    END
  END rb_data[278]
  PIN rb_data[279]
    DIRECTION OUTPUT ;
    USE SIGNAL ;
    PORT
      LAYER M4 ;
      RECT 0.00000 26.83200 0.02400 26.85600 ;
    END
  END rb_data[279]
  PIN rb_data[280]
    DIRECTION OUTPUT ;
    USE SIGNAL ;
    PORT
      LAYER M4 ;
      RECT 0.00000 26.92800 0.02400 26.95200 ;
    END
  END rb_data[280]
  PIN rb_data[281]
    DIRECTION OUTPUT ;
    USE SIGNAL ;
    PORT
      LAYER M4 ;
      RECT 0.00000 27.02400 0.02400 27.04800 ;
    END
  END rb_data[281]
  PIN rb_data[282]
    DIRECTION OUTPUT ;
    USE SIGNAL ;
    PORT
      LAYER M4 ;
      RECT 0.00000 27.12000 0.02400 27.14400 ;
    END
  END rb_data[282]
  PIN rb_data[283]
    DIRECTION OUTPUT ;
    USE SIGNAL ;
    PORT
      LAYER M4 ;
      RECT 0.00000 27.21600 0.02400 27.24000 ;
    END
  END rb_data[283]
  PIN rb_data[284]
    DIRECTION OUTPUT ;
    USE SIGNAL ;
    PORT
      LAYER M4 ;
      RECT 0.00000 27.31200 0.02400 27.33600 ;
    END
  END rb_data[284]
  PIN rb_data[285]
    DIRECTION OUTPUT ;
    USE SIGNAL ;
    PORT
      LAYER M4 ;
      RECT 0.00000 27.40800 0.02400 27.43200 ;
    END
  END rb_data[285]
  PIN rb_data[286]
    DIRECTION OUTPUT ;
    USE SIGNAL ;
    PORT
      LAYER M4 ;
      RECT 0.00000 27.50400 0.02400 27.52800 ;
    END
  END rb_data[286]
  PIN rb_data[287]
    DIRECTION OUTPUT ;
    USE SIGNAL ;
    PORT
      LAYER M4 ;
      RECT 0.00000 27.60000 0.02400 27.62400 ;
    END
  END rb_data[287]
  PIN rb_data[288]
    DIRECTION OUTPUT ;
    USE SIGNAL ;
    PORT
      LAYER M4 ;
      RECT 0.00000 27.69600 0.02400 27.72000 ;
    END
  END rb_data[288]
  PIN rb_data[289]
    DIRECTION OUTPUT ;
    USE SIGNAL ;
    PORT
      LAYER M4 ;
      RECT 0.00000 27.79200 0.02400 27.81600 ;
    END
  END rb_data[289]
  PIN rb_data[290]
    DIRECTION OUTPUT ;
    USE SIGNAL ;
    PORT
      LAYER M4 ;
      RECT 0.00000 27.88800 0.02400 27.91200 ;
    END
  END rb_data[290]
  PIN rb_data[291]
    DIRECTION OUTPUT ;
    USE SIGNAL ;
    PORT
      LAYER M4 ;
      RECT 0.00000 27.98400 0.02400 28.00800 ;
    END
  END rb_data[291]
  PIN rb_data[292]
    DIRECTION OUTPUT ;
    USE SIGNAL ;
    PORT
      LAYER M4 ;
      RECT 0.00000 28.08000 0.02400 28.10400 ;
    END
  END rb_data[292]
  PIN rb_data[293]
    DIRECTION OUTPUT ;
    USE SIGNAL ;
    PORT
      LAYER M4 ;
      RECT 0.00000 28.17600 0.02400 28.20000 ;
    END
  END rb_data[293]
  PIN rb_data[294]
    DIRECTION OUTPUT ;
    USE SIGNAL ;
    PORT
      LAYER M4 ;
      RECT 0.00000 28.27200 0.02400 28.29600 ;
    END
  END rb_data[294]
  PIN rb_data[295]
    DIRECTION OUTPUT ;
    USE SIGNAL ;
    PORT
      LAYER M4 ;
      RECT 0.00000 28.36800 0.02400 28.39200 ;
    END
  END rb_data[295]
  PIN rb_data[296]
    DIRECTION OUTPUT ;
    USE SIGNAL ;
    PORT
      LAYER M4 ;
      RECT 0.00000 28.46400 0.02400 28.48800 ;
    END
  END rb_data[296]
  PIN rb_data[297]
    DIRECTION OUTPUT ;
    USE SIGNAL ;
    PORT
      LAYER M4 ;
      RECT 0.00000 28.56000 0.02400 28.58400 ;
    END
  END rb_data[297]
  PIN rb_data[298]
    DIRECTION OUTPUT ;
    USE SIGNAL ;
    PORT
      LAYER M4 ;
      RECT 0.00000 28.65600 0.02400 28.68000 ;
    END
  END rb_data[298]
  PIN rb_data[299]
    DIRECTION OUTPUT ;
    USE SIGNAL ;
    PORT
      LAYER M4 ;
      RECT 0.00000 28.75200 0.02400 28.77600 ;
    END
  END rb_data[299]
  PIN rb_data[300]
    DIRECTION OUTPUT ;
    USE SIGNAL ;
    PORT
      LAYER M4 ;
      RECT 0.00000 28.84800 0.02400 28.87200 ;
    END
  END rb_data[300]
  PIN rb_data[301]
    DIRECTION OUTPUT ;
    USE SIGNAL ;
    PORT
      LAYER M4 ;
      RECT 0.00000 28.94400 0.02400 28.96800 ;
    END
  END rb_data[301]
  PIN rb_data[302]
    DIRECTION OUTPUT ;
    USE SIGNAL ;
    PORT
      LAYER M4 ;
      RECT 0.00000 29.04000 0.02400 29.06400 ;
    END
  END rb_data[302]
  PIN rb_data[303]
    DIRECTION OUTPUT ;
    USE SIGNAL ;
    PORT
      LAYER M4 ;
      RECT 0.00000 29.13600 0.02400 29.16000 ;
    END
  END rb_data[303]
  PIN rb_data[304]
    DIRECTION OUTPUT ;
    USE SIGNAL ;
    PORT
      LAYER M4 ;
      RECT 0.00000 29.23200 0.02400 29.25600 ;
    END
  END rb_data[304]
  PIN rb_data[305]
    DIRECTION OUTPUT ;
    USE SIGNAL ;
    PORT
      LAYER M4 ;
      RECT 0.00000 29.32800 0.02400 29.35200 ;
    END
  END rb_data[305]
  PIN rb_data[306]
    DIRECTION OUTPUT ;
    USE SIGNAL ;
    PORT
      LAYER M4 ;
      RECT 0.00000 29.42400 0.02400 29.44800 ;
    END
  END rb_data[306]
  PIN rb_data[307]
    DIRECTION OUTPUT ;
    USE SIGNAL ;
    PORT
      LAYER M4 ;
      RECT 0.00000 29.52000 0.02400 29.54400 ;
    END
  END rb_data[307]
  PIN rb_data[308]
    DIRECTION OUTPUT ;
    USE SIGNAL ;
    PORT
      LAYER M4 ;
      RECT 0.00000 29.61600 0.02400 29.64000 ;
    END
  END rb_data[308]
  PIN rb_data[309]
    DIRECTION OUTPUT ;
    USE SIGNAL ;
    PORT
      LAYER M4 ;
      RECT 0.00000 29.71200 0.02400 29.73600 ;
    END
  END rb_data[309]
  PIN rb_data[310]
    DIRECTION OUTPUT ;
    USE SIGNAL ;
    PORT
      LAYER M4 ;
      RECT 0.00000 29.80800 0.02400 29.83200 ;
    END
  END rb_data[310]
  PIN rb_data[311]
    DIRECTION OUTPUT ;
    USE SIGNAL ;
    PORT
      LAYER M4 ;
      RECT 0.00000 29.90400 0.02400 29.92800 ;
    END
  END rb_data[311]
  PIN rb_data[312]
    DIRECTION OUTPUT ;
    USE SIGNAL ;
    PORT
      LAYER M4 ;
      RECT 0.00000 30.00000 0.02400 30.02400 ;
    END
  END rb_data[312]
  PIN rb_data[313]
    DIRECTION OUTPUT ;
    USE SIGNAL ;
    PORT
      LAYER M4 ;
      RECT 0.00000 30.09600 0.02400 30.12000 ;
    END
  END rb_data[313]
  PIN rb_data[314]
    DIRECTION OUTPUT ;
    USE SIGNAL ;
    PORT
      LAYER M4 ;
      RECT 0.00000 30.19200 0.02400 30.21600 ;
    END
  END rb_data[314]
  PIN rb_data[315]
    DIRECTION OUTPUT ;
    USE SIGNAL ;
    PORT
      LAYER M4 ;
      RECT 0.00000 30.28800 0.02400 30.31200 ;
    END
  END rb_data[315]
  PIN rb_data[316]
    DIRECTION OUTPUT ;
    USE SIGNAL ;
    PORT
      LAYER M4 ;
      RECT 0.00000 30.38400 0.02400 30.40800 ;
    END
  END rb_data[316]
  PIN rb_data[317]
    DIRECTION OUTPUT ;
    USE SIGNAL ;
    PORT
      LAYER M4 ;
      RECT 0.00000 30.48000 0.02400 30.50400 ;
    END
  END rb_data[317]
  PIN rb_data[318]
    DIRECTION OUTPUT ;
    USE SIGNAL ;
    PORT
      LAYER M4 ;
      RECT 0.00000 30.57600 0.02400 30.60000 ;
    END
  END rb_data[318]
  PIN rb_data[319]
    DIRECTION OUTPUT ;
    USE SIGNAL ;
    PORT
      LAYER M4 ;
      RECT 0.00000 30.67200 0.02400 30.69600 ;
    END
  END rb_data[319]
  PIN rb_data[320]
    DIRECTION OUTPUT ;
    USE SIGNAL ;
    PORT
      LAYER M4 ;
      RECT 0.00000 30.76800 0.02400 30.79200 ;
    END
  END rb_data[320]
  PIN rb_data[321]
    DIRECTION OUTPUT ;
    USE SIGNAL ;
    PORT
      LAYER M4 ;
      RECT 0.00000 30.86400 0.02400 30.88800 ;
    END
  END rb_data[321]
  PIN rb_data[322]
    DIRECTION OUTPUT ;
    USE SIGNAL ;
    PORT
      LAYER M4 ;
      RECT 0.00000 30.96000 0.02400 30.98400 ;
    END
  END rb_data[322]
  PIN rb_data[323]
    DIRECTION OUTPUT ;
    USE SIGNAL ;
    PORT
      LAYER M4 ;
      RECT 0.00000 31.05600 0.02400 31.08000 ;
    END
  END rb_data[323]
  PIN rb_data[324]
    DIRECTION OUTPUT ;
    USE SIGNAL ;
    PORT
      LAYER M4 ;
      RECT 0.00000 31.15200 0.02400 31.17600 ;
    END
  END rb_data[324]
  PIN rb_data[325]
    DIRECTION OUTPUT ;
    USE SIGNAL ;
    PORT
      LAYER M4 ;
      RECT 0.00000 31.24800 0.02400 31.27200 ;
    END
  END rb_data[325]
  PIN rb_data[326]
    DIRECTION OUTPUT ;
    USE SIGNAL ;
    PORT
      LAYER M4 ;
      RECT 0.00000 31.34400 0.02400 31.36800 ;
    END
  END rb_data[326]
  PIN rb_data[327]
    DIRECTION OUTPUT ;
    USE SIGNAL ;
    PORT
      LAYER M4 ;
      RECT 0.00000 31.44000 0.02400 31.46400 ;
    END
  END rb_data[327]
  PIN rb_data[328]
    DIRECTION OUTPUT ;
    USE SIGNAL ;
    PORT
      LAYER M4 ;
      RECT 0.00000 31.53600 0.02400 31.56000 ;
    END
  END rb_data[328]
  PIN rb_data[329]
    DIRECTION OUTPUT ;
    USE SIGNAL ;
    PORT
      LAYER M4 ;
      RECT 0.00000 31.63200 0.02400 31.65600 ;
    END
  END rb_data[329]
  PIN rb_data[330]
    DIRECTION OUTPUT ;
    USE SIGNAL ;
    PORT
      LAYER M4 ;
      RECT 0.00000 31.72800 0.02400 31.75200 ;
    END
  END rb_data[330]
  PIN rb_data[331]
    DIRECTION OUTPUT ;
    USE SIGNAL ;
    PORT
      LAYER M4 ;
      RECT 0.00000 31.82400 0.02400 31.84800 ;
    END
  END rb_data[331]
  PIN rb_data[332]
    DIRECTION OUTPUT ;
    USE SIGNAL ;
    PORT
      LAYER M4 ;
      RECT 0.00000 31.92000 0.02400 31.94400 ;
    END
  END rb_data[332]
  PIN rb_data[333]
    DIRECTION OUTPUT ;
    USE SIGNAL ;
    PORT
      LAYER M4 ;
      RECT 0.00000 32.01600 0.02400 32.04000 ;
    END
  END rb_data[333]
  PIN rb_data[334]
    DIRECTION OUTPUT ;
    USE SIGNAL ;
    PORT
      LAYER M4 ;
      RECT 0.00000 32.11200 0.02400 32.13600 ;
    END
  END rb_data[334]
  PIN rb_data[335]
    DIRECTION OUTPUT ;
    USE SIGNAL ;
    PORT
      LAYER M4 ;
      RECT 0.00000 32.20800 0.02400 32.23200 ;
    END
  END rb_data[335]
  PIN rb_data[336]
    DIRECTION OUTPUT ;
    USE SIGNAL ;
    PORT
      LAYER M4 ;
      RECT 0.00000 32.30400 0.02400 32.32800 ;
    END
  END rb_data[336]
  PIN rb_data[337]
    DIRECTION OUTPUT ;
    USE SIGNAL ;
    PORT
      LAYER M4 ;
      RECT 0.00000 32.40000 0.02400 32.42400 ;
    END
  END rb_data[337]
  PIN rb_data[338]
    DIRECTION OUTPUT ;
    USE SIGNAL ;
    PORT
      LAYER M4 ;
      RECT 0.00000 32.49600 0.02400 32.52000 ;
    END
  END rb_data[338]
  PIN rb_data[339]
    DIRECTION OUTPUT ;
    USE SIGNAL ;
    PORT
      LAYER M4 ;
      RECT 0.00000 32.59200 0.02400 32.61600 ;
    END
  END rb_data[339]
  PIN rb_data[340]
    DIRECTION OUTPUT ;
    USE SIGNAL ;
    PORT
      LAYER M4 ;
      RECT 0.00000 32.68800 0.02400 32.71200 ;
    END
  END rb_data[340]
  PIN rb_data[341]
    DIRECTION OUTPUT ;
    USE SIGNAL ;
    PORT
      LAYER M4 ;
      RECT 0.00000 32.78400 0.02400 32.80800 ;
    END
  END rb_data[341]
  PIN rb_data[342]
    DIRECTION OUTPUT ;
    USE SIGNAL ;
    PORT
      LAYER M4 ;
      RECT 0.00000 32.88000 0.02400 32.90400 ;
    END
  END rb_data[342]
  PIN rb_data[343]
    DIRECTION OUTPUT ;
    USE SIGNAL ;
    PORT
      LAYER M4 ;
      RECT 0.00000 32.97600 0.02400 33.00000 ;
    END
  END rb_data[343]
  PIN rb_data[344]
    DIRECTION OUTPUT ;
    USE SIGNAL ;
    PORT
      LAYER M4 ;
      RECT 0.00000 33.07200 0.02400 33.09600 ;
    END
  END rb_data[344]
  PIN rb_data[345]
    DIRECTION OUTPUT ;
    USE SIGNAL ;
    PORT
      LAYER M4 ;
      RECT 0.00000 33.16800 0.02400 33.19200 ;
    END
  END rb_data[345]
  PIN rb_data[346]
    DIRECTION OUTPUT ;
    USE SIGNAL ;
    PORT
      LAYER M4 ;
      RECT 0.00000 33.26400 0.02400 33.28800 ;
    END
  END rb_data[346]
  PIN rb_data[347]
    DIRECTION OUTPUT ;
    USE SIGNAL ;
    PORT
      LAYER M4 ;
      RECT 0.00000 33.36000 0.02400 33.38400 ;
    END
  END rb_data[347]
  PIN rb_data[348]
    DIRECTION OUTPUT ;
    USE SIGNAL ;
    PORT
      LAYER M4 ;
      RECT 0.00000 33.45600 0.02400 33.48000 ;
    END
  END rb_data[348]
  PIN rb_data[349]
    DIRECTION OUTPUT ;
    USE SIGNAL ;
    PORT
      LAYER M4 ;
      RECT 0.00000 33.55200 0.02400 33.57600 ;
    END
  END rb_data[349]
  PIN rb_data[350]
    DIRECTION OUTPUT ;
    USE SIGNAL ;
    PORT
      LAYER M4 ;
      RECT 0.00000 33.64800 0.02400 33.67200 ;
    END
  END rb_data[350]
  PIN rb_data[351]
    DIRECTION OUTPUT ;
    USE SIGNAL ;
    PORT
      LAYER M4 ;
      RECT 0.00000 33.74400 0.02400 33.76800 ;
    END
  END rb_data[351]
  PIN rb_data[352]
    DIRECTION OUTPUT ;
    USE SIGNAL ;
    PORT
      LAYER M4 ;
      RECT 0.00000 33.84000 0.02400 33.86400 ;
    END
  END rb_data[352]
  PIN rb_data[353]
    DIRECTION OUTPUT ;
    USE SIGNAL ;
    PORT
      LAYER M4 ;
      RECT 0.00000 33.93600 0.02400 33.96000 ;
    END
  END rb_data[353]
  PIN rb_data[354]
    DIRECTION OUTPUT ;
    USE SIGNAL ;
    PORT
      LAYER M4 ;
      RECT 0.00000 34.03200 0.02400 34.05600 ;
    END
  END rb_data[354]
  PIN rb_data[355]
    DIRECTION OUTPUT ;
    USE SIGNAL ;
    PORT
      LAYER M4 ;
      RECT 0.00000 34.12800 0.02400 34.15200 ;
    END
  END rb_data[355]
  PIN rb_data[356]
    DIRECTION OUTPUT ;
    USE SIGNAL ;
    PORT
      LAYER M4 ;
      RECT 0.00000 34.22400 0.02400 34.24800 ;
    END
  END rb_data[356]
  PIN rb_data[357]
    DIRECTION OUTPUT ;
    USE SIGNAL ;
    PORT
      LAYER M4 ;
      RECT 0.00000 34.32000 0.02400 34.34400 ;
    END
  END rb_data[357]
  PIN rb_data[358]
    DIRECTION OUTPUT ;
    USE SIGNAL ;
    PORT
      LAYER M4 ;
      RECT 0.00000 34.41600 0.02400 34.44000 ;
    END
  END rb_data[358]
  PIN rb_data[359]
    DIRECTION OUTPUT ;
    USE SIGNAL ;
    PORT
      LAYER M4 ;
      RECT 0.00000 34.51200 0.02400 34.53600 ;
    END
  END rb_data[359]
  PIN rb_data[360]
    DIRECTION OUTPUT ;
    USE SIGNAL ;
    PORT
      LAYER M4 ;
      RECT 0.00000 34.60800 0.02400 34.63200 ;
    END
  END rb_data[360]
  PIN rb_data[361]
    DIRECTION OUTPUT ;
    USE SIGNAL ;
    PORT
      LAYER M4 ;
      RECT 0.00000 34.70400 0.02400 34.72800 ;
    END
  END rb_data[361]
  PIN rb_data[362]
    DIRECTION OUTPUT ;
    USE SIGNAL ;
    PORT
      LAYER M4 ;
      RECT 0.00000 34.80000 0.02400 34.82400 ;
    END
  END rb_data[362]
  PIN rb_data[363]
    DIRECTION OUTPUT ;
    USE SIGNAL ;
    PORT
      LAYER M4 ;
      RECT 0.00000 34.89600 0.02400 34.92000 ;
    END
  END rb_data[363]
  PIN rb_data[364]
    DIRECTION OUTPUT ;
    USE SIGNAL ;
    PORT
      LAYER M4 ;
      RECT 0.00000 34.99200 0.02400 35.01600 ;
    END
  END rb_data[364]
  PIN rb_data[365]
    DIRECTION OUTPUT ;
    USE SIGNAL ;
    PORT
      LAYER M4 ;
      RECT 0.00000 35.08800 0.02400 35.11200 ;
    END
  END rb_data[365]
  PIN rb_data[366]
    DIRECTION OUTPUT ;
    USE SIGNAL ;
    PORT
      LAYER M4 ;
      RECT 0.00000 35.18400 0.02400 35.20800 ;
    END
  END rb_data[366]
  PIN rb_data[367]
    DIRECTION OUTPUT ;
    USE SIGNAL ;
    PORT
      LAYER M4 ;
      RECT 0.00000 35.28000 0.02400 35.30400 ;
    END
  END rb_data[367]
  PIN rb_data[368]
    DIRECTION OUTPUT ;
    USE SIGNAL ;
    PORT
      LAYER M4 ;
      RECT 0.00000 35.37600 0.02400 35.40000 ;
    END
  END rb_data[368]
  PIN rb_data[369]
    DIRECTION OUTPUT ;
    USE SIGNAL ;
    PORT
      LAYER M4 ;
      RECT 0.00000 35.47200 0.02400 35.49600 ;
    END
  END rb_data[369]
  PIN rb_data[370]
    DIRECTION OUTPUT ;
    USE SIGNAL ;
    PORT
      LAYER M4 ;
      RECT 0.00000 35.56800 0.02400 35.59200 ;
    END
  END rb_data[370]
  PIN rb_data[371]
    DIRECTION OUTPUT ;
    USE SIGNAL ;
    PORT
      LAYER M4 ;
      RECT 0.00000 35.66400 0.02400 35.68800 ;
    END
  END rb_data[371]
  PIN rb_data[372]
    DIRECTION OUTPUT ;
    USE SIGNAL ;
    PORT
      LAYER M4 ;
      RECT 0.00000 35.76000 0.02400 35.78400 ;
    END
  END rb_data[372]
  PIN rb_data[373]
    DIRECTION OUTPUT ;
    USE SIGNAL ;
    PORT
      LAYER M4 ;
      RECT 0.00000 35.85600 0.02400 35.88000 ;
    END
  END rb_data[373]
  PIN rb_data[374]
    DIRECTION OUTPUT ;
    USE SIGNAL ;
    PORT
      LAYER M4 ;
      RECT 0.00000 35.95200 0.02400 35.97600 ;
    END
  END rb_data[374]
  PIN rb_data[375]
    DIRECTION OUTPUT ;
    USE SIGNAL ;
    PORT
      LAYER M4 ;
      RECT 0.00000 36.04800 0.02400 36.07200 ;
    END
  END rb_data[375]
  PIN rb_data[376]
    DIRECTION OUTPUT ;
    USE SIGNAL ;
    PORT
      LAYER M4 ;
      RECT 0.00000 36.14400 0.02400 36.16800 ;
    END
  END rb_data[376]
  PIN rb_data[377]
    DIRECTION OUTPUT ;
    USE SIGNAL ;
    PORT
      LAYER M4 ;
      RECT 0.00000 36.24000 0.02400 36.26400 ;
    END
  END rb_data[377]
  PIN rb_data[378]
    DIRECTION OUTPUT ;
    USE SIGNAL ;
    PORT
      LAYER M4 ;
      RECT 0.00000 36.33600 0.02400 36.36000 ;
    END
  END rb_data[378]
  PIN rb_data[379]
    DIRECTION OUTPUT ;
    USE SIGNAL ;
    PORT
      LAYER M4 ;
      RECT 0.00000 36.43200 0.02400 36.45600 ;
    END
  END rb_data[379]
  PIN rb_data[380]
    DIRECTION OUTPUT ;
    USE SIGNAL ;
    PORT
      LAYER M4 ;
      RECT 0.00000 36.52800 0.02400 36.55200 ;
    END
  END rb_data[380]
  PIN rb_data[381]
    DIRECTION OUTPUT ;
    USE SIGNAL ;
    PORT
      LAYER M4 ;
      RECT 0.00000 36.62400 0.02400 36.64800 ;
    END
  END rb_data[381]
  PIN rb_data[382]
    DIRECTION OUTPUT ;
    USE SIGNAL ;
    PORT
      LAYER M4 ;
      RECT 0.00000 36.72000 0.02400 36.74400 ;
    END
  END rb_data[382]
  PIN rb_data[383]
    DIRECTION OUTPUT ;
    USE SIGNAL ;
    PORT
      LAYER M4 ;
      RECT 0.00000 36.81600 0.02400 36.84000 ;
    END
  END rb_data[383]
  PIN rb_data[384]
    DIRECTION OUTPUT ;
    USE SIGNAL ;
    PORT
      LAYER M4 ;
      RECT 0.00000 36.91200 0.02400 36.93600 ;
    END
  END rb_data[384]
  PIN rb_data[385]
    DIRECTION OUTPUT ;
    USE SIGNAL ;
    PORT
      LAYER M4 ;
      RECT 0.00000 37.00800 0.02400 37.03200 ;
    END
  END rb_data[385]
  PIN rb_data[386]
    DIRECTION OUTPUT ;
    USE SIGNAL ;
    PORT
      LAYER M4 ;
      RECT 0.00000 37.10400 0.02400 37.12800 ;
    END
  END rb_data[386]
  PIN rb_data[387]
    DIRECTION OUTPUT ;
    USE SIGNAL ;
    PORT
      LAYER M4 ;
      RECT 0.00000 37.20000 0.02400 37.22400 ;
    END
  END rb_data[387]
  PIN rb_data[388]
    DIRECTION OUTPUT ;
    USE SIGNAL ;
    PORT
      LAYER M4 ;
      RECT 0.00000 37.29600 0.02400 37.32000 ;
    END
  END rb_data[388]
  PIN rb_data[389]
    DIRECTION OUTPUT ;
    USE SIGNAL ;
    PORT
      LAYER M4 ;
      RECT 0.00000 37.39200 0.02400 37.41600 ;
    END
  END rb_data[389]
  PIN rb_addr[0]
    DIRECTION INPUT ;
    USE SIGNAL ;
    PORT
      LAYER M4 ;
      RECT 0.00000 80.68800 0.02400 80.71200 ;
    END
  END rb_addr[0]
  PIN rb_addr[1]
    DIRECTION INPUT ;
    USE SIGNAL ;
    PORT
      LAYER M4 ;
      RECT 0.00000 80.78400 0.02400 80.80800 ;
    END
  END rb_addr[1]
  PIN rb_addr[2]
    DIRECTION INPUT ;
    USE SIGNAL ;
    PORT
      LAYER M4 ;
      RECT 0.00000 80.88000 0.02400 80.90400 ;
    END
  END rb_addr[2]
  PIN rb_addr[3]
    DIRECTION INPUT ;
    USE SIGNAL ;
    PORT
      LAYER M4 ;
      RECT 0.00000 80.97600 0.02400 81.00000 ;
    END
  END rb_addr[3]
  PIN rb_addr[4]
    DIRECTION INPUT ;
    USE SIGNAL ;
    PORT
      LAYER M4 ;
      RECT 0.00000 81.07200 0.02400 81.09600 ;
    END
  END rb_addr[4]
  PIN rb_addr[5]
    DIRECTION INPUT ;
    USE SIGNAL ;
    PORT
      LAYER M4 ;
      RECT 0.00000 81.16800 0.02400 81.19200 ;
    END
  END rb_addr[5]
  PIN rb_addr[6]
    DIRECTION INPUT ;
    USE SIGNAL ;
    PORT
      LAYER M4 ;
      RECT 0.00000 81.26400 0.02400 81.28800 ;
    END
  END rb_addr[6]
  PIN rb_addr[7]
    DIRECTION INPUT ;
    USE SIGNAL ;
    PORT
      LAYER M4 ;
      RECT 0.00000 81.36000 0.02400 81.38400 ;
    END
  END rb_addr[7]
  PIN we[0]
    DIRECTION INPUT ;
    USE SIGNAL ;
    PORT
      LAYER M4 ;
      RECT 0.00000 83.66400 0.02400 83.68800 ;
    END
  END we[0]
  PIN we[1]
    DIRECTION INPUT ;
    USE SIGNAL ;
    PORT
      LAYER M4 ;
      RECT 0.00000 83.76000 0.02400 83.78400 ;
    END
  END we[1]
  PIN clk
    DIRECTION INPUT ;
    USE SIGNAL ;
    PORT
      LAYER M4 ;
      RECT 0.00000 83.56800 0.02400 83.59200 ;
    END
  END clk
  PIN rb_en
    DIRECTION INPUT ;
    USE SIGNAL ;
    PORT
      LAYER M4 ;
      RECT 0.00000 83.85600 0.02400 83.88000 ;
    END
  END rb_en
  PIN rb_addr_q[0]
    DIRECTION OUTPUT ;
    USE SIGNAL ;
    PORT
      LAYER M4 ;
      RECT 0.00000 37.48800 0.02400 37.51200 ;
    END
  END rb_addr_q[0]
  PIN rb_addr_q[1]
    DIRECTION OUTPUT ;
    USE SIGNAL ;
    PORT
      LAYER M4 ;
      RECT 0.00000 37.58400 0.02400 37.60800 ;
    END
  END rb_addr_q[1]
  PIN rb_addr_q[2]
    DIRECTION OUTPUT ;
    USE SIGNAL ;
    PORT
      LAYER M4 ;
      RECT 0.00000 37.68000 0.02400 37.70400 ;
    END
  END rb_addr_q[2]
  PIN rb_addr_q[3]
    DIRECTION OUTPUT ;
    USE SIGNAL ;
    PORT
      LAYER M4 ;
      RECT 0.00000 37.77600 0.02400 37.80000 ;
    END
  END rb_addr_q[3]
  PIN rb_addr_q[4]
    DIRECTION OUTPUT ;
    USE SIGNAL ;
    PORT
      LAYER M4 ;
      RECT 0.00000 37.87200 0.02400 37.89600 ;
    END
  END rb_addr_q[4]
  PIN rb_addr_q[5]
    DIRECTION OUTPUT ;
    USE SIGNAL ;
    PORT
      LAYER M4 ;
      RECT 0.00000 37.96800 0.02400 37.99200 ;
    END
  END rb_addr_q[5]
  PIN rb_addr_q[6]
    DIRECTION OUTPUT ;
    USE SIGNAL ;
    PORT
      LAYER M4 ;
      RECT 0.00000 38.06400 0.02400 38.08800 ;
    END
  END rb_addr_q[6]
  PIN rb_addr_q[7]
    DIRECTION OUTPUT ;
    USE SIGNAL ;
    PORT
      LAYER M4 ;
      RECT 0.00000 38.16000 0.02400 38.18400 ;
    END
  END rb_addr_q[7]
  PIN VDD
    DIRECTION INOUT ;
    USE POWER ;
    PORT
      LAYER M4 ;
      RECT 0.04800 0.38400 50.68200 0.48000 ;
      RECT 0.04800 1.15200 50.68200 1.24800 ;
      RECT 0.04800 1.92000 50.68200 2.01600 ;
      RECT 0.04800 2.68800 50.68200 2.78400 ;
      RECT 0.04800 3.45600 50.68200 3.55200 ;
      RECT 0.04800 4.22400 50.68200 4.32000 ;
      RECT 0.04800 4.99200 50.68200 5.08800 ;
      RECT 0.04800 5.76000 50.68200 5.85600 ;
      RECT 0.04800 6.52800 50.68200 6.62400 ;
      RECT 0.04800 7.29600 50.68200 7.39200 ;
      RECT 0.04800 8.06400 50.68200 8.16000 ;
      RECT 0.04800 8.83200 50.68200 8.92800 ;
      RECT 0.04800 9.60000 50.68200 9.69600 ;
      RECT 0.04800 10.36800 50.68200 10.46400 ;
      RECT 0.04800 11.13600 50.68200 11.23200 ;
      RECT 0.04800 11.90400 50.68200 12.00000 ;
      RECT 0.04800 12.67200 50.68200 12.76800 ;
      RECT 0.04800 13.44000 50.68200 13.53600 ;
      RECT 0.04800 14.20800 50.68200 14.30400 ;
      RECT 0.04800 14.97600 50.68200 15.07200 ;
      RECT 0.04800 15.74400 50.68200 15.84000 ;
      RECT 0.04800 16.51200 50.68200 16.60800 ;
      RECT 0.04800 17.28000 50.68200 17.37600 ;
      RECT 0.04800 18.04800 50.68200 18.14400 ;
      RECT 0.04800 18.81600 50.68200 18.91200 ;
      RECT 0.04800 19.58400 50.68200 19.68000 ;
      RECT 0.04800 20.35200 50.68200 20.44800 ;
      RECT 0.04800 21.12000 50.68200 21.21600 ;
      RECT 0.04800 21.88800 50.68200 21.98400 ;
      RECT 0.04800 22.65600 50.68200 22.75200 ;
      RECT 0.04800 23.42400 50.68200 23.52000 ;
      RECT 0.04800 24.19200 50.68200 24.28800 ;
      RECT 0.04800 24.96000 50.68200 25.05600 ;
      RECT 0.04800 25.72800 50.68200 25.82400 ;
      RECT 0.04800 26.49600 50.68200 26.59200 ;
      RECT 0.04800 27.26400 50.68200 27.36000 ;
      RECT 0.04800 28.03200 50.68200 28.12800 ;
      RECT 0.04800 28.80000 50.68200 28.89600 ;
      RECT 0.04800 29.56800 50.68200 29.66400 ;
      RECT 0.04800 30.33600 50.68200 30.43200 ;
      RECT 0.04800 31.10400 50.68200 31.20000 ;
      RECT 0.04800 31.87200 50.68200 31.96800 ;
      RECT 0.04800 32.64000 50.68200 32.73600 ;
      RECT 0.04800 33.40800 50.68200 33.50400 ;
      RECT 0.04800 34.17600 50.68200 34.27200 ;
      RECT 0.04800 34.94400 50.68200 35.04000 ;
      RECT 0.04800 35.71200 50.68200 35.80800 ;
      RECT 0.04800 36.48000 50.68200 36.57600 ;
      RECT 0.04800 37.24800 50.68200 37.34400 ;
      RECT 0.04800 38.01600 50.68200 38.11200 ;
      RECT 0.04800 38.78400 50.68200 38.88000 ;
      RECT 0.04800 39.55200 50.68200 39.64800 ;
      RECT 0.04800 40.32000 50.68200 40.41600 ;
      RECT 0.04800 41.08800 50.68200 41.18400 ;
      RECT 0.04800 41.85600 50.68200 41.95200 ;
      RECT 0.04800 42.62400 50.68200 42.72000 ;
      RECT 0.04800 43.39200 50.68200 43.48800 ;
      RECT 0.04800 44.16000 50.68200 44.25600 ;
      RECT 0.04800 44.92800 50.68200 45.02400 ;
      RECT 0.04800 45.69600 50.68200 45.79200 ;
      RECT 0.04800 46.46400 50.68200 46.56000 ;
      RECT 0.04800 47.23200 50.68200 47.32800 ;
      RECT 0.04800 48.00000 50.68200 48.09600 ;
      RECT 0.04800 48.76800 50.68200 48.86400 ;
      RECT 0.04800 49.53600 50.68200 49.63200 ;
      RECT 0.04800 50.30400 50.68200 50.40000 ;
      RECT 0.04800 51.07200 50.68200 51.16800 ;
      RECT 0.04800 51.84000 50.68200 51.93600 ;
      RECT 0.04800 52.60800 50.68200 52.70400 ;
      RECT 0.04800 53.37600 50.68200 53.47200 ;
      RECT 0.04800 54.14400 50.68200 54.24000 ;
      RECT 0.04800 54.91200 50.68200 55.00800 ;
      RECT 0.04800 55.68000 50.68200 55.77600 ;
      RECT 0.04800 56.44800 50.68200 56.54400 ;
      RECT 0.04800 57.21600 50.68200 57.31200 ;
      RECT 0.04800 57.98400 50.68200 58.08000 ;
      RECT 0.04800 58.75200 50.68200 58.84800 ;
      RECT 0.04800 59.52000 50.68200 59.61600 ;
      RECT 0.04800 60.28800 50.68200 60.38400 ;
      RECT 0.04800 61.05600 50.68200 61.15200 ;
      RECT 0.04800 61.82400 50.68200 61.92000 ;
      RECT 0.04800 62.59200 50.68200 62.68800 ;
      RECT 0.04800 63.36000 50.68200 63.45600 ;
      RECT 0.04800 64.12800 50.68200 64.22400 ;
      RECT 0.04800 64.89600 50.68200 64.99200 ;
      RECT 0.04800 65.66400 50.68200 65.76000 ;
      RECT 0.04800 66.43200 50.68200 66.52800 ;
      RECT 0.04800 67.20000 50.68200 67.29600 ;
      RECT 0.04800 67.96800 50.68200 68.06400 ;
      RECT 0.04800 68.73600 50.68200 68.83200 ;
      RECT 0.04800 69.50400 50.68200 69.60000 ;
      RECT 0.04800 70.27200 50.68200 70.36800 ;
      RECT 0.04800 71.04000 50.68200 71.13600 ;
      RECT 0.04800 71.80800 50.68200 71.90400 ;
      RECT 0.04800 72.57600 50.68200 72.67200 ;
      RECT 0.04800 73.34400 50.68200 73.44000 ;
      RECT 0.04800 74.11200 50.68200 74.20800 ;
      RECT 0.04800 74.88000 50.68200 74.97600 ;
      RECT 0.04800 75.64800 50.68200 75.74400 ;
      RECT 0.04800 76.41600 50.68200 76.51200 ;
      RECT 0.04800 77.18400 50.68200 77.28000 ;
      RECT 0.04800 77.95200 50.68200 78.04800 ;
      RECT 0.04800 78.72000 50.68200 78.81600 ;
      RECT 0.04800 79.48800 50.68200 79.58400 ;
      RECT 0.04800 80.25600 50.68200 80.35200 ;
      RECT 0.04800 81.02400 50.68200 81.12000 ;
      RECT 0.04800 81.79200 50.68200 81.88800 ;
      RECT 0.04800 82.56000 50.68200 82.65600 ;
      RECT 0.04800 83.32800 50.68200 83.42400 ;
    END
  END VDD
  PIN VSS
    DIRECTION INOUT ;
    USE GROUND ;
    PORT
      LAYER M4 ;
      RECT 0.04800 0.00000 50.68200 0.09600 ;
      RECT 0.04800 0.76800 50.68200 0.86400 ;
      RECT 0.04800 1.53600 50.68200 1.63200 ;
      RECT 0.04800 2.30400 50.68200 2.40000 ;
      RECT 0.04800 3.07200 50.68200 3.16800 ;
      RECT 0.04800 3.84000 50.68200 3.93600 ;
      RECT 0.04800 4.60800 50.68200 4.70400 ;
      RECT 0.04800 5.37600 50.68200 5.47200 ;
      RECT 0.04800 6.14400 50.68200 6.24000 ;
      RECT 0.04800 6.91200 50.68200 7.00800 ;
      RECT 0.04800 7.68000 50.68200 7.77600 ;
      RECT 0.04800 8.44800 50.68200 8.54400 ;
      RECT 0.04800 9.21600 50.68200 9.31200 ;
      RECT 0.04800 9.98400 50.68200 10.08000 ;
      RECT 0.04800 10.75200 50.68200 10.84800 ;
      RECT 0.04800 11.52000 50.68200 11.61600 ;
      RECT 0.04800 12.28800 50.68200 12.38400 ;
      RECT 0.04800 13.05600 50.68200 13.15200 ;
      RECT 0.04800 13.82400 50.68200 13.92000 ;
      RECT 0.04800 14.59200 50.68200 14.68800 ;
      RECT 0.04800 15.36000 50.68200 15.45600 ;
      RECT 0.04800 16.12800 50.68200 16.22400 ;
      RECT 0.04800 16.89600 50.68200 16.99200 ;
      RECT 0.04800 17.66400 50.68200 17.76000 ;
      RECT 0.04800 18.43200 50.68200 18.52800 ;
      RECT 0.04800 19.20000 50.68200 19.29600 ;
      RECT 0.04800 19.96800 50.68200 20.06400 ;
      RECT 0.04800 20.73600 50.68200 20.83200 ;
      RECT 0.04800 21.50400 50.68200 21.60000 ;
      RECT 0.04800 22.27200 50.68200 22.36800 ;
      RECT 0.04800 23.04000 50.68200 23.13600 ;
      RECT 0.04800 23.80800 50.68200 23.90400 ;
      RECT 0.04800 24.57600 50.68200 24.67200 ;
      RECT 0.04800 25.34400 50.68200 25.44000 ;
      RECT 0.04800 26.11200 50.68200 26.20800 ;
      RECT 0.04800 26.88000 50.68200 26.97600 ;
      RECT 0.04800 27.64800 50.68200 27.74400 ;
      RECT 0.04800 28.41600 50.68200 28.51200 ;
      RECT 0.04800 29.18400 50.68200 29.28000 ;
      RECT 0.04800 29.95200 50.68200 30.04800 ;
      RECT 0.04800 30.72000 50.68200 30.81600 ;
      RECT 0.04800 31.48800 50.68200 31.58400 ;
      RECT 0.04800 32.25600 50.68200 32.35200 ;
      RECT 0.04800 33.02400 50.68200 33.12000 ;
      RECT 0.04800 33.79200 50.68200 33.88800 ;
      RECT 0.04800 34.56000 50.68200 34.65600 ;
      RECT 0.04800 35.32800 50.68200 35.42400 ;
      RECT 0.04800 36.09600 50.68200 36.19200 ;
      RECT 0.04800 36.86400 50.68200 36.96000 ;
      RECT 0.04800 37.63200 50.68200 37.72800 ;
      RECT 0.04800 38.40000 50.68200 38.49600 ;
      RECT 0.04800 39.16800 50.68200 39.26400 ;
      RECT 0.04800 39.93600 50.68200 40.03200 ;
      RECT 0.04800 40.70400 50.68200 40.80000 ;
      RECT 0.04800 41.47200 50.68200 41.56800 ;
      RECT 0.04800 42.24000 50.68200 42.33600 ;
      RECT 0.04800 43.00800 50.68200 43.10400 ;
      RECT 0.04800 43.77600 50.68200 43.87200 ;
      RECT 0.04800 44.54400 50.68200 44.64000 ;
      RECT 0.04800 45.31200 50.68200 45.40800 ;
      RECT 0.04800 46.08000 50.68200 46.17600 ;
      RECT 0.04800 46.84800 50.68200 46.94400 ;
      RECT 0.04800 47.61600 50.68200 47.71200 ;
      RECT 0.04800 48.38400 50.68200 48.48000 ;
      RECT 0.04800 49.15200 50.68200 49.24800 ;
      RECT 0.04800 49.92000 50.68200 50.01600 ;
      RECT 0.04800 50.68800 50.68200 50.78400 ;
      RECT 0.04800 51.45600 50.68200 51.55200 ;
      RECT 0.04800 52.22400 50.68200 52.32000 ;
      RECT 0.04800 52.99200 50.68200 53.08800 ;
      RECT 0.04800 53.76000 50.68200 53.85600 ;
      RECT 0.04800 54.52800 50.68200 54.62400 ;
      RECT 0.04800 55.29600 50.68200 55.39200 ;
      RECT 0.04800 56.06400 50.68200 56.16000 ;
      RECT 0.04800 56.83200 50.68200 56.92800 ;
      RECT 0.04800 57.60000 50.68200 57.69600 ;
      RECT 0.04800 58.36800 50.68200 58.46400 ;
      RECT 0.04800 59.13600 50.68200 59.23200 ;
      RECT 0.04800 59.90400 50.68200 60.00000 ;
      RECT 0.04800 60.67200 50.68200 60.76800 ;
      RECT 0.04800 61.44000 50.68200 61.53600 ;
      RECT 0.04800 62.20800 50.68200 62.30400 ;
      RECT 0.04800 62.97600 50.68200 63.07200 ;
      RECT 0.04800 63.74400 50.68200 63.84000 ;
      RECT 0.04800 64.51200 50.68200 64.60800 ;
      RECT 0.04800 65.28000 50.68200 65.37600 ;
      RECT 0.04800 66.04800 50.68200 66.14400 ;
      RECT 0.04800 66.81600 50.68200 66.91200 ;
      RECT 0.04800 67.58400 50.68200 67.68000 ;
      RECT 0.04800 68.35200 50.68200 68.44800 ;
      RECT 0.04800 69.12000 50.68200 69.21600 ;
      RECT 0.04800 69.88800 50.68200 69.98400 ;
      RECT 0.04800 70.65600 50.68200 70.75200 ;
      RECT 0.04800 71.42400 50.68200 71.52000 ;
      RECT 0.04800 72.19200 50.68200 72.28800 ;
      RECT 0.04800 72.96000 50.68200 73.05600 ;
      RECT 0.04800 73.72800 50.68200 73.82400 ;
      RECT 0.04800 74.49600 50.68200 74.59200 ;
      RECT 0.04800 75.26400 50.68200 75.36000 ;
      RECT 0.04800 76.03200 50.68200 76.12800 ;
      RECT 0.04800 76.80000 50.68200 76.89600 ;
      RECT 0.04800 77.56800 50.68200 77.66400 ;
      RECT 0.04800 78.33600 50.68200 78.43200 ;
      RECT 0.04800 79.10400 50.68200 79.20000 ;
      RECT 0.04800 79.87200 50.68200 79.96800 ;
      RECT 0.04800 80.64000 50.68200 80.73600 ;
      RECT 0.04800 81.40800 50.68200 81.50400 ;
      RECT 0.04800 82.17600 50.68200 82.27200 ;
      RECT 0.04800 82.94400 50.68200 83.04000 ;
      RECT 0.04800 83.71200 50.68200 83.80800 ;
    END
  END VSS
  OBS
    LAYER M1 ;
    RECT 0 0 50.73000 84.00000 ;
    LAYER M2 ;
    RECT 0 0 50.73000 84.00000 ;
    LAYER M3 ;
    RECT 0 0 50.73000 84.00000 ;
    LAYER M4 ;
    RECT 0 0 50.73000 84.00000 ;
  END
END fakeram7_256x390_g2_1w1r

END LIBRARY
